VERSION 5.8 ;
BUSBITCHARS "[]" ;
DIVIDERCHAR "/" ;
CLEARANCEMEASURE EUCLIDEAN ;

SITE gt2_6t
    SIZE 0.0420 BY 0.1440 ;
    CLASS CORE ;
    SYMMETRY Y ;
END gt2_6t

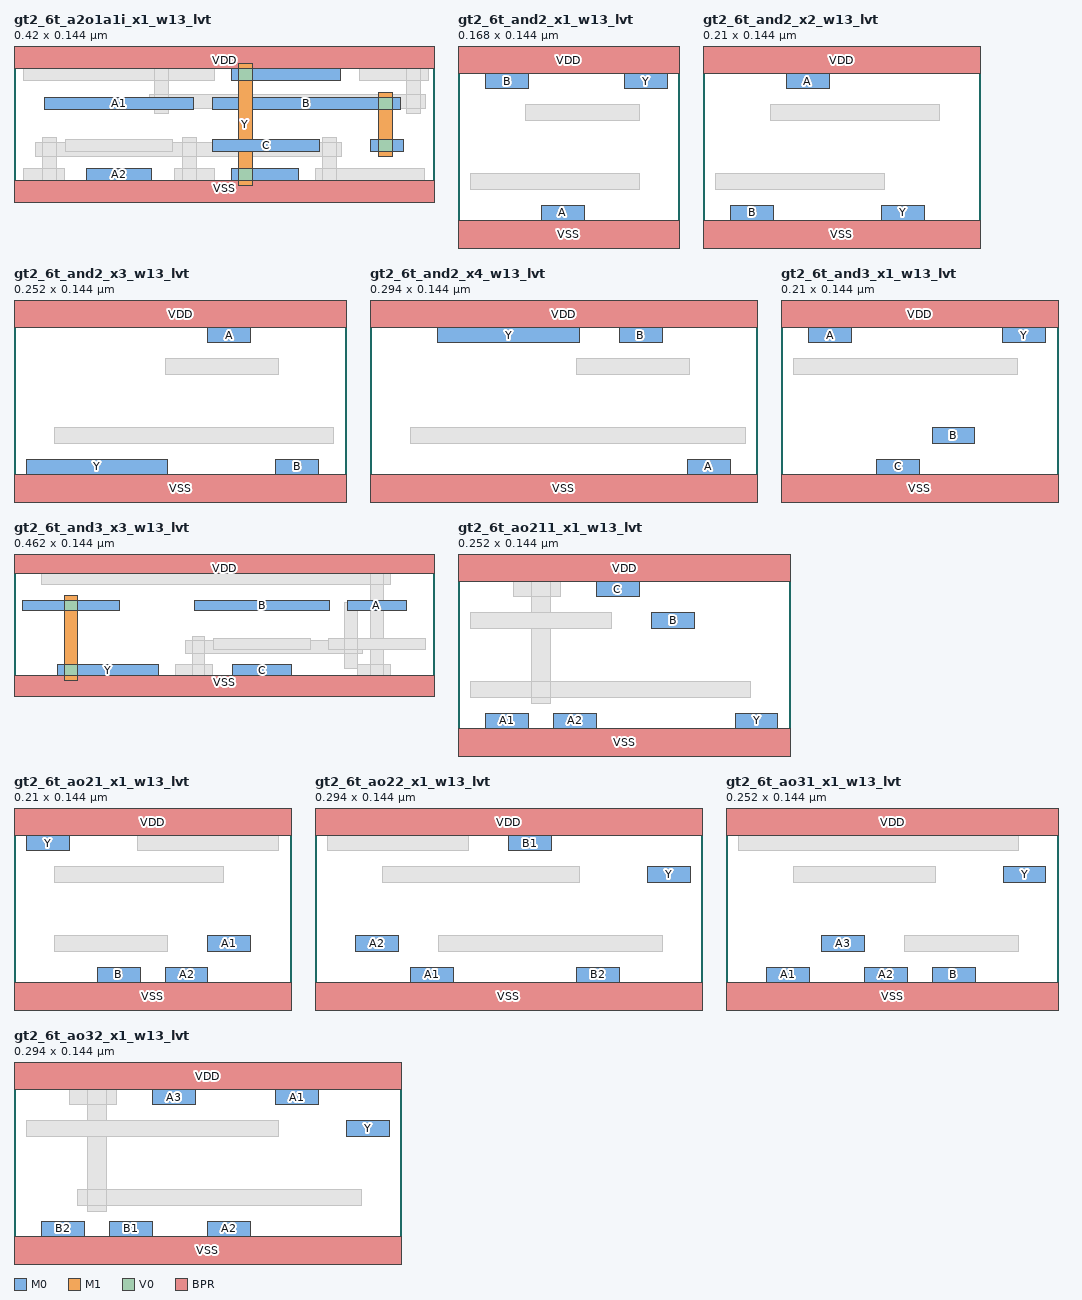
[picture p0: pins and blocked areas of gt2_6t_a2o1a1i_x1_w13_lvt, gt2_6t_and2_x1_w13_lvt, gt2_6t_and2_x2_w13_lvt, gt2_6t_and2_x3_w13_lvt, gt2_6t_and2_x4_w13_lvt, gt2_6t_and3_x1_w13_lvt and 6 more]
MACRO gt2_6t_a2o1a1i_x1_w13_lvt
  CLASS CORE ;
  ORIGIN 0 0 ;
  FOREIGN gt2_6t_a2o1a1i_x1_w13_lvt 0 0 ;
  SIZE 0.4200 BY 0.1440 ;
  SYMMETRY X Y ;
  SITE gt2_6t ;
  PIN A1
    DIRECTION INPUT ;
    USE SIGNAL ;
    PORT
      LAYER M0 ;
        RECT 0.0305 0.0870 0.1795 0.0990 ;
    END
  END A1
  PIN A2
    DIRECTION INPUT ;
    USE SIGNAL ;
    PORT
      LAYER M0 ;
        RECT 0.0725 0.0160 0.1375 0.0280 ;
    END
  END A2
  PIN B
    DIRECTION INPUT ;
    USE SIGNAL ;
    PORT
      LAYER M1 ;
        RECT 0.3640 0.0400 0.3780 0.1040 ;
      LAYER M0 ;
        RECT 0.3560 0.0450 0.3895 0.0570 ;
        RECT 0.1985 0.0870 0.3860 0.0990 ;
      LAYER V0 ;
        RECT 0.3640 0.0450 0.3780 0.0570 ;
        RECT 0.3640 0.0870 0.3780 0.0990 ;
    END
  END B
  PIN C
    DIRECTION INPUT ;
    USE SIGNAL ;
    PORT
      LAYER M0 ;
        RECT 0.1985 0.0450 0.3055 0.0570 ;
    END
  END C
  PIN Y
    DIRECTION OUTPUT ;
    USE SIGNAL ;
    PORT
      LAYER M1 ;
        RECT 0.2240 0.0110 0.2380 0.1330 ;
      LAYER M0 ;
        RECT 0.2175 0.0160 0.2845 0.0280 ;
        RECT 0.2175 0.1160 0.3265 0.1280 ;
      LAYER V0 ;
        RECT 0.2240 0.0160 0.2380 0.0280 ;
        RECT 0.2240 0.1160 0.2380 0.1280 ;
    END
  END Y
  PIN VDD
    DIRECTION INOUT ;
    USE POWER ;
    SHAPE ABUTMENT ;
    PORT
      LAYER BPR ;
        RECT 0.0000 0.1280 0.4200 0.1600 ;
    END
  END VDD
  PIN VSS
    DIRECTION INOUT ;
    USE GROUND ;
    SHAPE ABUTMENT ;
    PORT
      LAYER BPR ;
        RECT 0.0000 -0.0160 0.4200 0.0160 ;
    END
  END VSS
  OBS
    LAYER M2 ;
      RECT 0.0210 0.0400 0.3270 0.0540 ;
      RECT 0.1350 0.0880 0.4110 0.1020 ;
    LAYER M1 ;
      RECT 0.0280 0.0110 0.0420 0.0590 ;
      RECT 0.1680 0.0110 0.1820 0.0590 ;
      RECT 0.3080 0.0110 0.3220 0.0590 ;
      RECT 0.1400 0.0830 0.1540 0.1330 ;
      RECT 0.3920 0.0830 0.4060 0.1330 ;
    LAYER M0 ;
      RECT 0.0095 0.0160 0.0500 0.0280 ;
      RECT 0.1600 0.0160 0.2005 0.0280 ;
      RECT 0.3015 0.0160 0.4105 0.0280 ;
      RECT 0.0515 0.0450 0.1585 0.0570 ;
      RECT 0.0095 0.1160 0.2005 0.1280 ;
      RECT 0.3455 0.1160 0.4140 0.1280 ;
    LAYER V1 ;
      RECT 0.0280 0.0400 0.0420 0.0540 ;
      RECT 0.1680 0.0400 0.1820 0.0540 ;
      RECT 0.3080 0.0400 0.3220 0.0540 ;
      RECT 0.1400 0.0880 0.1540 0.1020 ;
      RECT 0.3920 0.0880 0.4060 0.1020 ;
    LAYER V0 ;
      RECT 0.0280 0.0160 0.0420 0.0280 ;
      RECT 0.1680 0.0160 0.1820 0.0280 ;
      RECT 0.3080 0.0160 0.3220 0.0280 ;
      RECT 0.1400 0.1160 0.1540 0.1280 ;
      RECT 0.3920 0.1160 0.4060 0.1280 ;
  END
END gt2_6t_a2o1a1i_x1_w13_lvt

MACRO gt2_6t_and2_x1_w13_lvt
  CLASS CORE ;
  ORIGIN 0 0 ;
  FOREIGN gt2_6t_and2_x1_w13_lvt 0 0 ;
  SIZE 0.1680 BY 0.1440 ;
  SYMMETRY X Y ;
  SITE gt2_6t ;
  PIN A
    DIRECTION INPUT ;
    USE SIGNAL ;
    PORT
      LAYER M0 ;
        RECT 0.0630 0.0160 0.0955 0.0280 ;
    END
  END A
  PIN B
    DIRECTION INPUT ;
    USE SIGNAL ;
    PORT
      LAYER M0 ;
        RECT 0.0210 0.1160 0.0535 0.1280 ;
    END
  END B
  PIN Y
    DIRECTION OUTPUT ;
    USE SIGNAL ;
    PORT
      LAYER M0 ;
        RECT 0.1260 0.1160 0.1585 0.1280 ;
    END
  END Y
  PIN VDD
    DIRECTION INOUT ;
    USE POWER ;
    SHAPE ABUTMENT ;
    PORT
      LAYER BPR ;
        RECT 0.0000 0.1280 0.1680 0.1600 ;
    END
  END VDD
  PIN VSS
    DIRECTION INOUT ;
    USE GROUND ;
    SHAPE ABUTMENT ;
    PORT
      LAYER BPR ;
        RECT 0.0000 -0.0160 0.1680 0.0160 ;
    END
  END VSS
  OBS
    LAYER M0 ;
      RECT 0.0095 0.0400 0.1375 0.0520 ;
      RECT 0.0515 0.0920 0.1375 0.1040 ;
  END
END gt2_6t_and2_x1_w13_lvt

MACRO gt2_6t_and2_x2_w13_lvt
  CLASS CORE ;
  ORIGIN 0 0 ;
  FOREIGN gt2_6t_and2_x2_w13_lvt 0 0 ;
  SIZE 0.2100 BY 0.1440 ;
  SYMMETRY X Y ;
  SITE gt2_6t ;
  PIN A
    DIRECTION INPUT ;
    USE SIGNAL ;
    PORT
      LAYER M0 ;
        RECT 0.0630 0.1160 0.0955 0.1280 ;
    END
  END A
  PIN B
    DIRECTION INPUT ;
    USE SIGNAL ;
    PORT
      LAYER M0 ;
        RECT 0.0210 0.0160 0.0535 0.0280 ;
    END
  END B
  PIN Y
    DIRECTION OUTPUT ;
    USE SIGNAL ;
    PORT
      LAYER M0 ;
        RECT 0.1355 0.0160 0.1680 0.0280 ;
    END
  END Y
  PIN VDD
    DIRECTION INOUT ;
    USE POWER ;
    SHAPE ABUTMENT ;
    PORT
      LAYER BPR ;
        RECT 0.0000 0.1280 0.2100 0.1600 ;
    END
  END VDD
  PIN VSS
    DIRECTION INOUT ;
    USE GROUND ;
    SHAPE ABUTMENT ;
    PORT
      LAYER BPR ;
        RECT 0.0000 -0.0160 0.2100 0.0160 ;
    END
  END VSS
  OBS
    LAYER M0 ;
      RECT 0.0095 0.0400 0.1375 0.0520 ;
      RECT 0.0515 0.0920 0.1795 0.1040 ;
  END
END gt2_6t_and2_x2_w13_lvt

MACRO gt2_6t_and2_x3_w13_lvt
  CLASS CORE ;
  ORIGIN 0 0 ;
  FOREIGN gt2_6t_and2_x3_w13_lvt 0 0 ;
  SIZE 0.2520 BY 0.1440 ;
  SYMMETRY X Y ;
  SITE gt2_6t ;
  PIN A
    DIRECTION INPUT ;
    USE SIGNAL ;
    PORT
      LAYER M0 ;
        RECT 0.1470 0.1160 0.1795 0.1280 ;
    END
  END A
  PIN B
    DIRECTION INPUT ;
    USE SIGNAL ;
    PORT
      LAYER M0 ;
        RECT 0.1985 0.0160 0.2310 0.0280 ;
    END
  END B
  PIN Y
    DIRECTION OUTPUT ;
    USE SIGNAL ;
    PORT
      LAYER M0 ;
        RECT 0.0095 0.0160 0.1165 0.0280 ;
    END
  END Y
  PIN VDD
    DIRECTION INOUT ;
    USE POWER ;
    SHAPE ABUTMENT ;
    PORT
      LAYER BPR ;
        RECT 0.0000 0.1280 0.2520 0.1600 ;
    END
  END VDD
  PIN VSS
    DIRECTION INOUT ;
    USE GROUND ;
    SHAPE ABUTMENT ;
    PORT
      LAYER BPR ;
        RECT 0.0000 -0.0160 0.2520 0.0160 ;
    END
  END VSS
  OBS
    LAYER M0 ;
      RECT 0.0305 0.0400 0.2425 0.0520 ;
      RECT 0.1145 0.0920 0.2005 0.1040 ;
  END
END gt2_6t_and2_x3_w13_lvt

MACRO gt2_6t_and2_x4_w13_lvt
  CLASS CORE ;
  ORIGIN 0 0 ;
  FOREIGN gt2_6t_and2_x4_w13_lvt 0 0 ;
  SIZE 0.2940 BY 0.1440 ;
  SYMMETRY X Y ;
  SITE gt2_6t ;
  PIN A
    DIRECTION INPUT ;
    USE SIGNAL ;
    PORT
      LAYER M0 ;
        RECT 0.2405 0.0160 0.2730 0.0280 ;
    END
  END A
  PIN B
    DIRECTION INPUT ;
    USE SIGNAL ;
    PORT
      LAYER M0 ;
        RECT 0.1890 0.1160 0.2215 0.1280 ;
    END
  END B
  PIN Y
    DIRECTION OUTPUT ;
    USE SIGNAL ;
    PORT
      LAYER M0 ;
        RECT 0.0515 0.1160 0.1585 0.1280 ;
    END
  END Y
  PIN VDD
    DIRECTION INOUT ;
    USE POWER ;
    SHAPE ABUTMENT ;
    PORT
      LAYER BPR ;
        RECT 0.0000 0.1280 0.2940 0.1600 ;
    END
  END VDD
  PIN VSS
    DIRECTION INOUT ;
    USE GROUND ;
    SHAPE ABUTMENT ;
    PORT
      LAYER BPR ;
        RECT 0.0000 -0.0160 0.2940 0.0160 ;
    END
  END VSS
  OBS
    LAYER M0 ;
      RECT 0.0305 0.0400 0.2845 0.0520 ;
      RECT 0.1565 0.0920 0.2425 0.1040 ;
  END
END gt2_6t_and2_x4_w13_lvt

MACRO gt2_6t_and3_x1_w13_lvt
  CLASS CORE ;
  ORIGIN 0 0 ;
  FOREIGN gt2_6t_and3_x1_w13_lvt 0 0 ;
  SIZE 0.2100 BY 0.1440 ;
  SYMMETRY X Y ;
  SITE gt2_6t ;
  PIN A
    DIRECTION INPUT ;
    USE SIGNAL ;
    PORT
      LAYER M0 ;
        RECT 0.0210 0.1160 0.0535 0.1280 ;
    END
  END A
  PIN B
    DIRECTION INPUT ;
    USE SIGNAL ;
    PORT
      LAYER M0 ;
        RECT 0.1145 0.0400 0.1470 0.0520 ;
    END
  END B
  PIN C
    DIRECTION INPUT ;
    USE SIGNAL ;
    PORT
      LAYER M0 ;
        RECT 0.0725 0.0160 0.1050 0.0280 ;
    END
  END C
  PIN Y
    DIRECTION OUTPUT ;
    USE SIGNAL ;
    PORT
      LAYER M0 ;
        RECT 0.1680 0.1160 0.2005 0.1280 ;
    END
  END Y
  PIN VDD
    DIRECTION INOUT ;
    USE POWER ;
    SHAPE ABUTMENT ;
    PORT
      LAYER BPR ;
        RECT 0.0000 0.1280 0.2100 0.1600 ;
    END
  END VDD
  PIN VSS
    DIRECTION INOUT ;
    USE GROUND ;
    SHAPE ABUTMENT ;
    PORT
      LAYER BPR ;
        RECT 0.0000 -0.0160 0.2100 0.0160 ;
    END
  END VSS
  OBS
    LAYER M0 ;
      RECT 0.0095 0.0920 0.1795 0.1040 ;
  END
END gt2_6t_and3_x1_w13_lvt

MACRO gt2_6t_and3_x3_w13_lvt
  CLASS CORE ;
  ORIGIN 0 0 ;
  FOREIGN gt2_6t_and3_x3_w13_lvt 0 0 ;
  SIZE 0.4620 BY 0.1440 ;
  SYMMETRY X Y ;
  SITE gt2_6t ;
  PIN A
    DIRECTION INPUT ;
    USE SIGNAL ;
    PORT
      LAYER M0 ;
        RECT 0.3665 0.0870 0.4315 0.0990 ;
    END
  END A
  PIN B
    DIRECTION INPUT ;
    USE SIGNAL ;
    PORT
      LAYER M0 ;
        RECT 0.1985 0.0870 0.3475 0.0990 ;
    END
  END B
  PIN C
    DIRECTION INPUT ;
    USE SIGNAL ;
    PORT
      LAYER M0 ;
        RECT 0.2405 0.0160 0.3055 0.0280 ;
    END
  END C
  PIN Y
    DIRECTION OUTPUT ;
    USE SIGNAL ;
    PORT
      LAYER M1 ;
        RECT 0.0560 0.0110 0.0700 0.1040 ;
      LAYER M0 ;
        RECT 0.0480 0.0160 0.1585 0.0280 ;
        RECT 0.0095 0.0870 0.1165 0.0990 ;
      LAYER V0 ;
        RECT 0.0560 0.0160 0.0700 0.0280 ;
        RECT 0.0560 0.0870 0.0700 0.0990 ;
    END
  END Y
  PIN VDD
    DIRECTION INOUT ;
    USE POWER ;
    SHAPE ABUTMENT ;
    PORT
      LAYER BPR ;
        RECT 0.0000 0.1280 0.4620 0.1600 ;
    END
  END VDD
  PIN VSS
    DIRECTION INOUT ;
    USE GROUND ;
    SHAPE ABUTMENT ;
    PORT
      LAYER BPR ;
        RECT 0.0000 -0.0160 0.4620 0.0160 ;
    END
  END VSS
  OBS
    LAYER M2 ;
      RECT 0.1890 0.0400 0.3830 0.0540 ;
    LAYER M1 ;
      RECT 0.1960 0.0110 0.2100 0.0590 ;
      RECT 0.3640 0.0240 0.3780 0.0960 ;
      RECT 0.3920 0.0110 0.4060 0.1330 ;
    LAYER M0 ;
      RECT 0.1775 0.0160 0.2180 0.0280 ;
      RECT 0.3455 0.0450 0.4525 0.0570 ;
      RECT 0.2195 0.0450 0.3265 0.0570 ;
      RECT 0.3780 0.0160 0.4140 0.0280 ;
      RECT 0.0305 0.1160 0.4140 0.1280 ;
    LAYER V1 ;
      RECT 0.1960 0.0400 0.2100 0.0540 ;
      RECT 0.3640 0.0400 0.3780 0.0540 ;
    LAYER V0 ;
      RECT 0.1960 0.0160 0.2100 0.0280 ;
      RECT 0.3640 0.0450 0.3780 0.0570 ;
      RECT 0.3920 0.0160 0.4060 0.0280 ;
      RECT 0.3920 0.1160 0.4060 0.1280 ;
  END
END gt2_6t_and3_x3_w13_lvt

MACRO gt2_6t_ao211_x1_w13_lvt
  CLASS CORE ;
  ORIGIN 0 0 ;
  FOREIGN gt2_6t_ao211_x1_w13_lvt 0 0 ;
  SIZE 0.2520 BY 0.1440 ;
  SYMMETRY X Y ;
  SITE gt2_6t ;
  PIN A1
    DIRECTION INPUT ;
    USE SIGNAL ;
    PORT
      LAYER M0 ;
        RECT 0.0210 0.0160 0.0535 0.0280 ;
    END
  END A1
  PIN A2
    DIRECTION INPUT ;
    USE SIGNAL ;
    PORT
      LAYER M0 ;
        RECT 0.0725 0.0160 0.1050 0.0280 ;
    END
  END A2
  PIN B
    DIRECTION INPUT ;
    USE SIGNAL ;
    PORT
      LAYER M0 ;
        RECT 0.1470 0.0920 0.1795 0.1040 ;
    END
  END B
  PIN C
    DIRECTION INPUT ;
    USE SIGNAL ;
    PORT
      LAYER M0 ;
        RECT 0.1050 0.1160 0.1375 0.1280 ;
    END
  END C
  PIN Y
    DIRECTION OUTPUT ;
    USE SIGNAL ;
    PORT
      LAYER M0 ;
        RECT 0.2100 0.0160 0.2425 0.0280 ;
    END
  END Y
  PIN VDD
    DIRECTION INOUT ;
    USE POWER ;
    SHAPE ABUTMENT ;
    PORT
      LAYER BPR ;
        RECT 0.0000 0.1280 0.2520 0.1600 ;
    END
  END VDD
  PIN VSS
    DIRECTION INOUT ;
    USE GROUND ;
    SHAPE ABUTMENT ;
    PORT
      LAYER BPR ;
        RECT 0.0000 -0.0160 0.2520 0.0160 ;
    END
  END VSS
  OBS
    LAYER M1 ;
      RECT 0.0560 0.0350 0.0700 0.1330 ;
    LAYER M0 ;
      RECT 0.0095 0.0400 0.2215 0.0520 ;
      RECT 0.0420 0.1160 0.0780 0.1280 ;
      RECT 0.0095 0.0920 0.1165 0.1040 ;
    LAYER V0 ;
      RECT 0.0560 0.0400 0.0700 0.0520 ;
      RECT 0.0560 0.1160 0.0700 0.1280 ;
  END
END gt2_6t_ao211_x1_w13_lvt

MACRO gt2_6t_ao21_x1_w13_lvt
  CLASS CORE ;
  ORIGIN 0 0 ;
  FOREIGN gt2_6t_ao21_x1_w13_lvt 0 0 ;
  SIZE 0.2100 BY 0.1440 ;
  SYMMETRY X Y ;
  SITE gt2_6t ;
  PIN A1
    DIRECTION INPUT ;
    USE SIGNAL ;
    PORT
      LAYER M0 ;
        RECT 0.1470 0.0400 0.1795 0.0520 ;
    END
  END A1
  PIN A2
    DIRECTION INPUT ;
    USE SIGNAL ;
    PORT
      LAYER M0 ;
        RECT 0.1145 0.0160 0.1470 0.0280 ;
    END
  END A2
  PIN B
    DIRECTION INPUT ;
    USE SIGNAL ;
    PORT
      LAYER M0 ;
        RECT 0.0630 0.0160 0.0955 0.0280 ;
    END
  END B
  PIN Y
    DIRECTION OUTPUT ;
    USE SIGNAL ;
    PORT
      LAYER M0 ;
        RECT 0.0095 0.1160 0.0420 0.1280 ;
    END
  END Y
  PIN VDD
    DIRECTION INOUT ;
    USE POWER ;
    SHAPE ABUTMENT ;
    PORT
      LAYER BPR ;
        RECT 0.0000 0.1280 0.2100 0.1600 ;
    END
  END VDD
  PIN VSS
    DIRECTION INOUT ;
    USE GROUND ;
    SHAPE ABUTMENT ;
    PORT
      LAYER BPR ;
        RECT 0.0000 -0.0160 0.2100 0.0160 ;
    END
  END VSS
  OBS
    LAYER M0 ;
      RECT 0.0305 0.0400 0.1165 0.0520 ;
      RECT 0.0305 0.0920 0.1585 0.1040 ;
      RECT 0.0935 0.1160 0.2005 0.1280 ;
  END
END gt2_6t_ao21_x1_w13_lvt

MACRO gt2_6t_ao22_x1_w13_lvt
  CLASS CORE ;
  ORIGIN 0 0 ;
  FOREIGN gt2_6t_ao22_x1_w13_lvt 0 0 ;
  SIZE 0.2940 BY 0.1440 ;
  SYMMETRY X Y ;
  SITE gt2_6t ;
  PIN A1
    DIRECTION INPUT ;
    USE SIGNAL ;
    PORT
      LAYER M0 ;
        RECT 0.0725 0.0160 0.1050 0.0280 ;
    END
  END A1
  PIN A2
    DIRECTION INPUT ;
    USE SIGNAL ;
    PORT
      LAYER M0 ;
        RECT 0.0305 0.0400 0.0630 0.0520 ;
    END
  END A2
  PIN B1
    DIRECTION INPUT ;
    USE SIGNAL ;
    PORT
      LAYER M0 ;
        RECT 0.1470 0.1160 0.1795 0.1280 ;
    END
  END B1
  PIN B2
    DIRECTION INPUT ;
    USE SIGNAL ;
    PORT
      LAYER M0 ;
        RECT 0.1985 0.0160 0.2310 0.0280 ;
    END
  END B2
  PIN Y
    DIRECTION OUTPUT ;
    USE SIGNAL ;
    PORT
      LAYER M0 ;
        RECT 0.2520 0.0920 0.2845 0.1040 ;
    END
  END Y
  PIN VDD
    DIRECTION INOUT ;
    USE POWER ;
    SHAPE ABUTMENT ;
    PORT
      LAYER BPR ;
        RECT 0.0000 0.1280 0.2940 0.1600 ;
    END
  END VDD
  PIN VSS
    DIRECTION INOUT ;
    USE GROUND ;
    SHAPE ABUTMENT ;
    PORT
      LAYER BPR ;
        RECT 0.0000 -0.0160 0.2940 0.0160 ;
    END
  END VSS
  OBS
    LAYER M0 ;
      RECT 0.0935 0.0400 0.2635 0.0520 ;
      RECT 0.0095 0.1160 0.1165 0.1280 ;
      RECT 0.0515 0.0920 0.2005 0.1040 ;
  END
END gt2_6t_ao22_x1_w13_lvt

MACRO gt2_6t_ao31_x1_w13_lvt
  CLASS CORE ;
  ORIGIN 0 0 ;
  FOREIGN gt2_6t_ao31_x1_w13_lvt 0 0 ;
  SIZE 0.2520 BY 0.1440 ;
  SYMMETRY X Y ;
  SITE gt2_6t ;
  PIN A1
    DIRECTION INPUT ;
    USE SIGNAL ;
    PORT
      LAYER M0 ;
        RECT 0.0305 0.0160 0.0630 0.0280 ;
    END
  END A1
  PIN A2
    DIRECTION INPUT ;
    USE SIGNAL ;
    PORT
      LAYER M0 ;
        RECT 0.1050 0.0160 0.1375 0.0280 ;
    END
  END A2
  PIN A3
    DIRECTION INPUT ;
    USE SIGNAL ;
    PORT
      LAYER M0 ;
        RECT 0.0725 0.0400 0.1050 0.0520 ;
    END
  END A3
  PIN B
    DIRECTION INPUT ;
    USE SIGNAL ;
    PORT
      LAYER M0 ;
        RECT 0.1565 0.0160 0.1890 0.0280 ;
    END
  END B
  PIN Y
    DIRECTION OUTPUT ;
    USE SIGNAL ;
    PORT
      LAYER M0 ;
        RECT 0.2100 0.0920 0.2425 0.1040 ;
    END
  END Y
  PIN VDD
    DIRECTION INOUT ;
    USE POWER ;
    SHAPE ABUTMENT ;
    PORT
      LAYER BPR ;
        RECT 0.0000 0.1280 0.2520 0.1600 ;
    END
  END VDD
  PIN VSS
    DIRECTION INOUT ;
    USE GROUND ;
    SHAPE ABUTMENT ;
    PORT
      LAYER BPR ;
        RECT 0.0000 -0.0160 0.2520 0.0160 ;
    END
  END VSS
  OBS
    LAYER M0 ;
      RECT 0.1355 0.0400 0.2215 0.0520 ;
      RECT 0.0095 0.1160 0.2215 0.1280 ;
      RECT 0.0515 0.0920 0.1585 0.1040 ;
  END
END gt2_6t_ao31_x1_w13_lvt

MACRO gt2_6t_ao32_x1_w13_lvt
  CLASS CORE ;
  ORIGIN 0 0 ;
  FOREIGN gt2_6t_ao32_x1_w13_lvt 0 0 ;
  SIZE 0.2940 BY 0.1440 ;
  SYMMETRY X Y ;
  SITE gt2_6t ;
  PIN A1
    DIRECTION INPUT ;
    USE SIGNAL ;
    PORT
      LAYER M0 ;
        RECT 0.1985 0.1160 0.2310 0.1280 ;
    END
  END A1
  PIN A2
    DIRECTION INPUT ;
    USE SIGNAL ;
    PORT
      LAYER M0 ;
        RECT 0.1470 0.0160 0.1795 0.0280 ;
    END
  END A2
  PIN A3
    DIRECTION INPUT ;
    USE SIGNAL ;
    PORT
      LAYER M0 ;
        RECT 0.1050 0.1160 0.1375 0.1280 ;
    END
  END A3
  PIN B1
    DIRECTION INPUT ;
    USE SIGNAL ;
    PORT
      LAYER M0 ;
        RECT 0.0725 0.0160 0.1050 0.0280 ;
    END
  END B1
  PIN B2
    DIRECTION INPUT ;
    USE SIGNAL ;
    PORT
      LAYER M0 ;
        RECT 0.0210 0.0160 0.0535 0.0280 ;
    END
  END B2
  PIN Y
    DIRECTION OUTPUT ;
    USE SIGNAL ;
    PORT
      LAYER M0 ;
        RECT 0.2520 0.0920 0.2845 0.1040 ;
    END
  END Y
  PIN VDD
    DIRECTION INOUT ;
    USE POWER ;
    SHAPE ABUTMENT ;
    PORT
      LAYER BPR ;
        RECT 0.0000 0.1280 0.2940 0.1600 ;
    END
  END VDD
  PIN VSS
    DIRECTION INOUT ;
    USE GROUND ;
    SHAPE ABUTMENT ;
    PORT
      LAYER BPR ;
        RECT 0.0000 -0.0160 0.2940 0.0160 ;
    END
  END VSS
  OBS
    LAYER M1 ;
      RECT 0.0560 0.0350 0.0700 0.1330 ;
    LAYER M0 ;
      RECT 0.0480 0.0400 0.2635 0.0520 ;
      RECT 0.0420 0.1160 0.0780 0.1280 ;
      RECT 0.0095 0.0920 0.2005 0.1040 ;
    LAYER V0 ;
      RECT 0.0560 0.0400 0.0700 0.0520 ;
      RECT 0.0560 0.1160 0.0700 0.1280 ;
  END
END gt2_6t_ao32_x1_w13_lvt

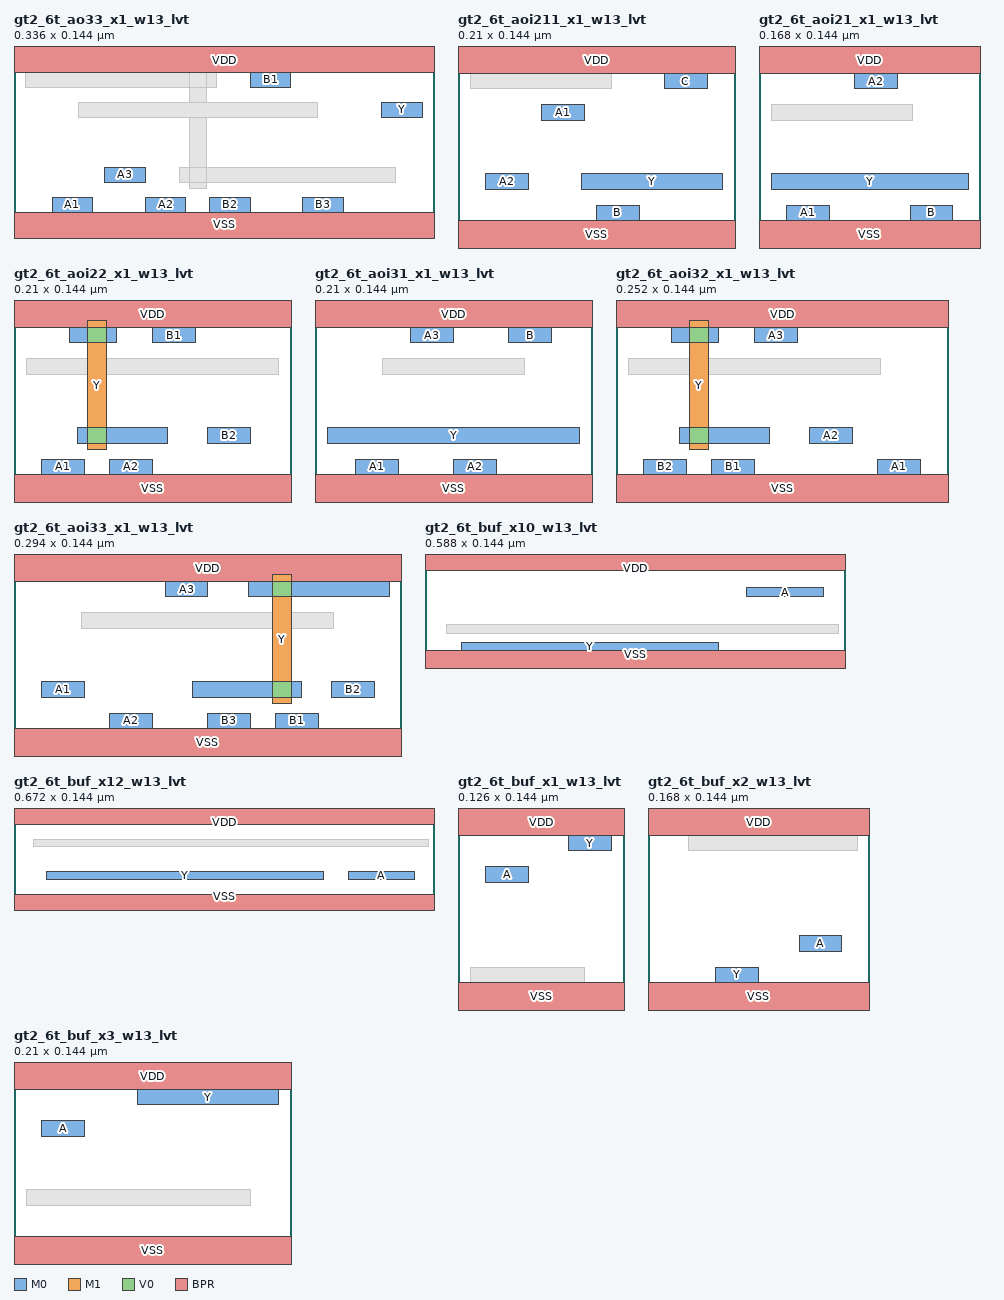
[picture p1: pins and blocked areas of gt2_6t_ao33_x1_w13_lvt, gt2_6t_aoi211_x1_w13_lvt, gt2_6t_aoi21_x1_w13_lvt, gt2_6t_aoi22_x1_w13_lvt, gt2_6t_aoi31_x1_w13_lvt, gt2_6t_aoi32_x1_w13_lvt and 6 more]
MACRO gt2_6t_ao33_x1_w13_lvt
  CLASS CORE ;
  ORIGIN 0 0 ;
  FOREIGN gt2_6t_ao33_x1_w13_lvt 0 0 ;
  SIZE 0.3360 BY 0.1440 ;
  SYMMETRY X Y ;
  SITE gt2_6t ;
  PIN A1
    DIRECTION INPUT ;
    USE SIGNAL ;
    PORT
      LAYER M0 ;
        RECT 0.0305 0.0160 0.0630 0.0280 ;
    END
  END A1
  PIN A2
    DIRECTION INPUT ;
    USE SIGNAL ;
    PORT
      LAYER M0 ;
        RECT 0.1050 0.0160 0.1375 0.0280 ;
    END
  END A2
  PIN A3
    DIRECTION INPUT ;
    USE SIGNAL ;
    PORT
      LAYER M0 ;
        RECT 0.0725 0.0400 0.1050 0.0520 ;
    END
  END A3
  PIN B1
    DIRECTION INPUT ;
    USE SIGNAL ;
    PORT
      LAYER M0 ;
        RECT 0.1890 0.1160 0.2215 0.1280 ;
    END
  END B1
  PIN B2
    DIRECTION INPUT ;
    USE SIGNAL ;
    PORT
      LAYER M0 ;
        RECT 0.1565 0.0160 0.1890 0.0280 ;
    END
  END B2
  PIN B3
    DIRECTION INPUT ;
    USE SIGNAL ;
    PORT
      LAYER M0 ;
        RECT 0.2310 0.0160 0.2635 0.0280 ;
    END
  END B3
  PIN Y
    DIRECTION OUTPUT ;
    USE SIGNAL ;
    PORT
      LAYER M0 ;
        RECT 0.2940 0.0920 0.3265 0.1040 ;
    END
  END Y
  PIN VDD
    DIRECTION INOUT ;
    USE POWER ;
    SHAPE ABUTMENT ;
    PORT
      LAYER BPR ;
        RECT 0.0000 0.1280 0.3360 0.1600 ;
    END
  END VDD
  PIN VSS
    DIRECTION INOUT ;
    USE GROUND ;
    SHAPE ABUTMENT ;
    PORT
      LAYER BPR ;
        RECT 0.0000 -0.0160 0.3360 0.0160 ;
    END
  END VSS
  OBS
    LAYER M1 ;
      RECT 0.1400 0.0350 0.1540 0.1330 ;
    LAYER M0 ;
      RECT 0.1320 0.0400 0.3055 0.0520 ;
      RECT 0.0095 0.1160 0.1620 0.1280 ;
      RECT 0.0515 0.0920 0.2425 0.1040 ;
    LAYER V0 ;
      RECT 0.1400 0.0400 0.1540 0.0520 ;
      RECT 0.1400 0.1160 0.1540 0.1280 ;
  END
END gt2_6t_ao33_x1_w13_lvt

MACRO gt2_6t_aoi211_x1_w13_lvt
  CLASS CORE ;
  ORIGIN 0 0 ;
  FOREIGN gt2_6t_aoi211_x1_w13_lvt 0 0 ;
  SIZE 0.2100 BY 0.1440 ;
  SYMMETRY X Y ;
  SITE gt2_6t ;
  PIN A1
    DIRECTION INPUT ;
    USE SIGNAL ;
    PORT
      LAYER M0 ;
        RECT 0.0630 0.0920 0.0955 0.1040 ;
    END
  END A1
  PIN A2
    DIRECTION INPUT ;
    USE SIGNAL ;
    PORT
      LAYER M0 ;
        RECT 0.0210 0.0400 0.0535 0.0520 ;
    END
  END A2
  PIN B
    DIRECTION INPUT ;
    USE SIGNAL ;
    PORT
      LAYER M0 ;
        RECT 0.1050 0.0160 0.1375 0.0280 ;
    END
  END B
  PIN C
    DIRECTION INPUT ;
    USE SIGNAL ;
    PORT
      LAYER M0 ;
        RECT 0.1565 0.1160 0.1890 0.1280 ;
    END
  END C
  PIN Y
    DIRECTION OUTPUT ;
    USE SIGNAL ;
    PORT
      LAYER M0 ;
        RECT 0.0935 0.0400 0.2005 0.0520 ;
    END
  END Y
  PIN VDD
    DIRECTION INOUT ;
    USE POWER ;
    SHAPE ABUTMENT ;
    PORT
      LAYER BPR ;
        RECT 0.0000 0.1280 0.2100 0.1600 ;
    END
  END VDD
  PIN VSS
    DIRECTION INOUT ;
    USE GROUND ;
    SHAPE ABUTMENT ;
    PORT
      LAYER BPR ;
        RECT 0.0000 -0.0160 0.2100 0.0160 ;
    END
  END VSS
  OBS
    LAYER M0 ;
      RECT 0.0095 0.1160 0.1165 0.1280 ;
  END
END gt2_6t_aoi211_x1_w13_lvt

MACRO gt2_6t_aoi21_x1_w13_lvt
  CLASS CORE ;
  ORIGIN 0 0 ;
  FOREIGN gt2_6t_aoi21_x1_w13_lvt 0 0 ;
  SIZE 0.1680 BY 0.1440 ;
  SYMMETRY X Y ;
  SITE gt2_6t ;
  PIN A1
    DIRECTION INPUT ;
    USE SIGNAL ;
    PORT
      LAYER M0 ;
        RECT 0.0210 0.0160 0.0535 0.0280 ;
    END
  END A1
  PIN A2
    DIRECTION INPUT ;
    USE SIGNAL ;
    PORT
      LAYER M0 ;
        RECT 0.0725 0.1160 0.1050 0.1280 ;
    END
  END A2
  PIN B
    DIRECTION INPUT ;
    USE SIGNAL ;
    PORT
      LAYER M0 ;
        RECT 0.1145 0.0160 0.1470 0.0280 ;
    END
  END B
  PIN Y
    DIRECTION OUTPUT ;
    USE SIGNAL ;
    PORT
      LAYER M0 ;
        RECT 0.0095 0.0400 0.1585 0.0520 ;
    END
  END Y
  PIN VDD
    DIRECTION INOUT ;
    USE POWER ;
    SHAPE ABUTMENT ;
    PORT
      LAYER BPR ;
        RECT 0.0000 0.1280 0.1680 0.1600 ;
    END
  END VDD
  PIN VSS
    DIRECTION INOUT ;
    USE GROUND ;
    SHAPE ABUTMENT ;
    PORT
      LAYER BPR ;
        RECT 0.0000 -0.0160 0.1680 0.0160 ;
    END
  END VSS
  OBS
    LAYER M0 ;
      RECT 0.0095 0.0920 0.1165 0.1040 ;
  END
END gt2_6t_aoi21_x1_w13_lvt


MACRO gt2_6t_aoi22_x1_w13_lvt
  CLASS CORE ;
  ORIGIN 0 0 ;
  FOREIGN gt2_6t_aoi22_x1_w13_lvt 0 0 ;
  SIZE 0.2100 BY 0.1440 ;
  SYMMETRY X Y ;
  SITE gt2_6t ;
  PIN A1
    DIRECTION INPUT ;
    USE SIGNAL ;
    PORT
      LAYER M0 ;
        RECT 0.0210 0.0160 0.0535 0.0280 ;
    END
  END A1
  PIN A2
    DIRECTION INPUT ;
    USE SIGNAL ;
    PORT
      LAYER M0 ;
        RECT 0.0725 0.0160 0.1050 0.0280 ;
    END
  END A2
  PIN B1
    DIRECTION INPUT ;
    USE SIGNAL ;
    PORT
      LAYER M0 ;
        RECT 0.1050 0.1160 0.1375 0.1280 ;
    END
  END B1
  PIN B2
    DIRECTION INPUT ;
    USE SIGNAL ;
    PORT
      LAYER M0 ;
        RECT 0.1470 0.0400 0.1795 0.0520 ;
    END
  END B2
  PIN Y
    DIRECTION OUTPUT ;
    USE SIGNAL ;
    PORT
      LAYER M1 ;
        RECT 0.0560 0.0350 0.0700 0.1330 ;
      LAYER M0 ;
        RECT 0.0480 0.0400 0.1165 0.0520 ;
        RECT 0.0420 0.1160 0.0780 0.1280 ;
      LAYER V0 ;
        RECT 0.0560 0.0400 0.0700 0.0520 ;
        RECT 0.0560 0.1160 0.0700 0.1280 ;
    END
  END Y
  PIN VDD
    DIRECTION INOUT ;
    USE POWER ;
    SHAPE ABUTMENT ;
    PORT
      LAYER BPR ;
        RECT 0.0000 0.1280 0.2100 0.1600 ;
    END
  END VDD
  PIN VSS
    DIRECTION INOUT ;
    USE GROUND ;
    SHAPE ABUTMENT ;
    PORT
      LAYER BPR ;
        RECT 0.0000 -0.0160 0.2100 0.0160 ;
    END
  END VSS
  OBS
    LAYER M0 ;
      RECT 0.0095 0.0920 0.2005 0.1040 ;
  END
END gt2_6t_aoi22_x1_w13_lvt


MACRO gt2_6t_aoi31_x1_w13_lvt
  CLASS CORE ;
  ORIGIN 0 0 ;
  FOREIGN gt2_6t_aoi31_x1_w13_lvt 0 0 ;
  SIZE 0.2100 BY 0.1440 ;
  SYMMETRY X Y ;
  SITE gt2_6t ;
  PIN A1
    DIRECTION INPUT ;
    USE SIGNAL ;
    PORT
      LAYER M0 ;
        RECT 0.0305 0.0160 0.0630 0.0280 ;
    END
  END A1
  PIN A2
    DIRECTION INPUT ;
    USE SIGNAL ;
    PORT
      LAYER M0 ;
        RECT 0.1050 0.0160 0.1375 0.0280 ;
    END
  END A2
  PIN A3
    DIRECTION INPUT ;
    USE SIGNAL ;
    PORT
      LAYER M0 ;
        RECT 0.0725 0.1160 0.1050 0.1280 ;
    END
  END A3
  PIN B
    DIRECTION INPUT ;
    USE SIGNAL ;
    PORT
      LAYER M0 ;
        RECT 0.1470 0.1160 0.1795 0.1280 ;
    END
  END B
  PIN Y
    DIRECTION OUTPUT ;
    USE SIGNAL ;
    PORT
      LAYER M0 ;
        RECT 0.0095 0.0400 0.2005 0.0520 ;
    END
  END Y
  PIN VDD
    DIRECTION INOUT ;
    USE POWER ;
    SHAPE ABUTMENT ;
    PORT
      LAYER BPR ;
        RECT 0.0000 0.1280 0.2100 0.1600 ;
    END
  END VDD
  PIN VSS
    DIRECTION INOUT ;
    USE GROUND ;
    SHAPE ABUTMENT ;
    PORT
      LAYER BPR ;
        RECT 0.0000 -0.0160 0.2100 0.0160 ;
    END
  END VSS
  OBS
    LAYER M0 ;
      RECT 0.0515 0.0920 0.1585 0.1040 ;
  END
END gt2_6t_aoi31_x1_w13_lvt

MACRO gt2_6t_aoi32_x1_w13_lvt
  CLASS CORE ;
  ORIGIN 0 0 ;
  FOREIGN gt2_6t_aoi32_x1_w13_lvt 0 0 ;
  SIZE 0.2520 BY 0.1440 ;
  SYMMETRY X Y ;
  SITE gt2_6t ;
  PIN A1
    DIRECTION INPUT ;
    USE SIGNAL ;
    PORT
      LAYER M0 ;
        RECT 0.1985 0.0160 0.2310 0.0280 ;
    END
  END A1
  PIN A2
    DIRECTION INPUT ;
    USE SIGNAL ;
    PORT
      LAYER M0 ;
        RECT 0.1470 0.0400 0.1795 0.0520 ;
    END
  END A2
  PIN A3
    DIRECTION INPUT ;
    USE SIGNAL ;
    PORT
      LAYER M0 ;
        RECT 0.1050 0.1160 0.1375 0.1280 ;
    END
  END A3
  PIN B1
    DIRECTION INPUT ;
    USE SIGNAL ;
    PORT
      LAYER M0 ;
        RECT 0.0725 0.0160 0.1050 0.0280 ;
    END
  END B1
  PIN B2
    DIRECTION INPUT ;
    USE SIGNAL ;
    PORT
      LAYER M0 ;
        RECT 0.0210 0.0160 0.0535 0.0280 ;
    END
  END B2
  PIN Y
    DIRECTION OUTPUT ;
    USE SIGNAL ;
    PORT
      LAYER M1 ;
        RECT 0.0560 0.0350 0.0700 0.1330 ;
      LAYER M0 ;
        RECT 0.0480 0.0400 0.1165 0.0520 ;
        RECT 0.0420 0.1160 0.0780 0.1280 ;
      LAYER V0 ;
        RECT 0.0560 0.0400 0.0700 0.0520 ;
        RECT 0.0560 0.1160 0.0700 0.1280 ;
    END
  END Y
  PIN VDD
    DIRECTION INOUT ;
    USE POWER ;
    SHAPE ABUTMENT ;
    PORT
      LAYER BPR ;
        RECT 0.0000 0.1280 0.2520 0.1600 ;
    END
  END VDD
  PIN VSS
    DIRECTION INOUT ;
    USE GROUND ;
    SHAPE ABUTMENT ;
    PORT
      LAYER BPR ;
        RECT 0.0000 -0.0160 0.2520 0.0160 ;
    END
  END VSS
  OBS
    LAYER M0 ;
      RECT 0.0095 0.0920 0.2005 0.1040 ;
  END
END gt2_6t_aoi32_x1_w13_lvt

MACRO gt2_6t_aoi33_x1_w13_lvt
  CLASS CORE ;
  ORIGIN 0 0 ;
  FOREIGN gt2_6t_aoi33_x1_w13_lvt 0 0 ;
  SIZE 0.2940 BY 0.1440 ;
  SYMMETRY X Y ;
  SITE gt2_6t ;
  PIN A1
    DIRECTION INPUT ;
    USE SIGNAL ;
    PORT
      LAYER M0 ;
        RECT 0.0210 0.0400 0.0535 0.0520 ;
    END
  END A1
  PIN A2
    DIRECTION INPUT ;
    USE SIGNAL ;
    PORT
      LAYER M0 ;
        RECT 0.0725 0.0160 0.1050 0.0280 ;
    END
  END A2
  PIN A3
    DIRECTION INPUT ;
    USE SIGNAL ;
    PORT
      LAYER M0 ;
        RECT 0.1145 0.1160 0.1470 0.1280 ;
    END
  END A3
  PIN B1
    DIRECTION INPUT ;
    USE SIGNAL ;
    PORT
      LAYER M0 ;
        RECT 0.1985 0.0160 0.2310 0.0280 ;
    END
  END B1
  PIN B2
    DIRECTION INPUT ;
    USE SIGNAL ;
    PORT
      LAYER M0 ;
        RECT 0.2405 0.0400 0.2730 0.0520 ;
    END
  END B2
  PIN B3
    DIRECTION INPUT ;
    USE SIGNAL ;
    PORT
      LAYER M0 ;
        RECT 0.1470 0.0160 0.1795 0.0280 ;
    END
  END B3
  PIN Y
    DIRECTION OUTPUT ;
    USE SIGNAL ;
    PORT
      LAYER M1 ;
        RECT 0.1960 0.0350 0.2100 0.1330 ;
      LAYER M0 ;
        RECT 0.1355 0.0400 0.2180 0.0520 ;
        RECT 0.1775 0.1160 0.2845 0.1280 ;
      LAYER V0 ;
        RECT 0.1960 0.0400 0.2100 0.0520 ;
        RECT 0.1960 0.1160 0.2100 0.1280 ;
    END
  END Y
  PIN VDD
    DIRECTION INOUT ;
    USE POWER ;
    SHAPE ABUTMENT ;
    PORT
      LAYER BPR ;
        RECT 0.0000 0.1280 0.2940 0.1600 ;
    END
  END VDD
  PIN VSS
    DIRECTION INOUT ;
    USE GROUND ;
    SHAPE ABUTMENT ;
    PORT
      LAYER BPR ;
        RECT 0.0000 -0.0160 0.2940 0.0160 ;
    END
  END VSS
  OBS
    LAYER M0 ;
      RECT 0.0515 0.0920 0.2425 0.1040 ;
  END
END gt2_6t_aoi33_x1_w13_lvt

MACRO gt2_6t_buf_x10_w13_lvt
  CLASS CORE ;
  ORIGIN 0 0 ;
  FOREIGN gt2_6t_buf_x10_w13_lvt 0 0 ;
  SIZE 0.5880 BY 0.1440 ;
  SYMMETRY X Y ;
  SITE gt2_6t ;
  PIN A
    DIRECTION INPUT ;
    USE SIGNAL ;
    PORT
      LAYER M0 ;
        RECT 0.4505 0.0920 0.5575 0.1040 ;
    END
  END A
  PIN Y
    DIRECTION OUTPUT ;
    USE SIGNAL ;
    PORT
      LAYER M0 ;
        RECT 0.0515 0.0160 0.4105 0.0280 ;
    END
  END Y
  PIN VDD
    DIRECTION INOUT ;
    USE POWER ;
    SHAPE ABUTMENT ;
    PORT
      LAYER BPR ;
        RECT 0.0000 0.1280 0.5880 0.1600 ;
    END
  END VDD
  PIN VSS
    DIRECTION INOUT ;
    USE GROUND ;
    SHAPE ABUTMENT ;
    PORT
      LAYER BPR ;
        RECT 0.0000 -0.0160 0.5880 0.0160 ;
    END
  END VSS
  OBS
    LAYER M0 ;
      RECT 0.0305 0.0400 0.5785 0.0520 ;
  END
END gt2_6t_buf_x10_w13_lvt

MACRO gt2_6t_buf_x12_w13_lvt
  CLASS CORE ;
  ORIGIN 0 0 ;
  FOREIGN gt2_6t_buf_x12_w13_lvt 0 0 ;
  SIZE 0.6720 BY 0.1440 ;
  SYMMETRY X Y ;
  SITE gt2_6t ;
  PIN A
    DIRECTION INPUT ;
    USE SIGNAL ;
    PORT
      LAYER M0 ;
        RECT 0.5345 0.0400 0.6415 0.0520 ;
    END
  END A
  PIN Y
    DIRECTION OUTPUT ;
    USE SIGNAL ;
    PORT
      LAYER M0 ;
        RECT 0.0515 0.0400 0.4945 0.0520 ;
    END
  END Y
  PIN VDD
    DIRECTION INOUT ;
    USE POWER ;
    SHAPE ABUTMENT ;
    PORT
      LAYER BPR ;
        RECT 0.0000 0.1280 0.6720 0.1600 ;
    END
  END VDD
  PIN VSS
    DIRECTION INOUT ;
    USE GROUND ;
    SHAPE ABUTMENT ;
    PORT
      LAYER BPR ;
        RECT 0.0000 -0.0160 0.6720 0.0160 ;
    END
  END VSS
  OBS
    LAYER M0 ;
      RECT 0.0305 0.0920 0.6625 0.1040 ;
  END
END gt2_6t_buf_x12_w13_lvt

MACRO gt2_6t_buf_x1_w13_lvt
  CLASS CORE ;
  ORIGIN 0 0 ;
  FOREIGN gt2_6t_buf_x1_w13_lvt 0 0 ;
  SIZE 0.1260 BY 0.1440 ;
  SYMMETRY X Y ;
  SITE gt2_6t ;
  PIN A
    DIRECTION INPUT ;
    USE SIGNAL ;
    PORT
      LAYER M0 ;
        RECT 0.0210 0.0920 0.0535 0.1040 ;
    END
  END A
  PIN Y
    DIRECTION OUTPUT ;
    USE SIGNAL ;
    PORT
      LAYER M0 ;
        RECT 0.0840 0.1160 0.1165 0.1280 ;
    END
  END Y
  PIN VDD
    DIRECTION INOUT ;
    USE POWER ;
    SHAPE ABUTMENT ;
    PORT
      LAYER BPR ;
        RECT 0.0000 0.1280 0.1260 0.1600 ;
    END
  END VDD
  PIN VSS
    DIRECTION INOUT ;
    USE GROUND ;
    SHAPE ABUTMENT ;
    PORT
      LAYER BPR ;
        RECT 0.0000 -0.0160 0.1260 0.0160 ;
    END
  END VSS
  OBS
    LAYER M0 ;
      RECT 0.0095 0.0160 0.0955 0.0280 ;
  END
END gt2_6t_buf_x1_w13_lvt

MACRO gt2_6t_buf_x2_w13_lvt
  CLASS CORE ;
  ORIGIN 0 0 ;
  FOREIGN gt2_6t_buf_x2_w13_lvt 0 0 ;
  SIZE 0.1680 BY 0.1440 ;
  SYMMETRY X Y ;
  SITE gt2_6t ;
  PIN A
    DIRECTION INPUT ;
    USE SIGNAL ;
    PORT
      LAYER M0 ;
        RECT 0.1145 0.0400 0.1470 0.0520 ;
    END
  END A
  PIN Y
    DIRECTION OUTPUT ;
    USE SIGNAL ;
    PORT
      LAYER M0 ;
        RECT 0.0515 0.0160 0.0840 0.0280 ;
    END
  END Y
  PIN VDD
    DIRECTION INOUT ;
    USE POWER ;
    SHAPE ABUTMENT ;
    PORT
      LAYER BPR ;
        RECT 0.0000 0.1280 0.1680 0.1600 ;
    END
  END VDD
  PIN VSS
    DIRECTION INOUT ;
    USE GROUND ;
    SHAPE ABUTMENT ;
    PORT
      LAYER BPR ;
        RECT 0.0000 -0.0160 0.1680 0.0160 ;
    END
  END VSS
  OBS
    LAYER M0 ;
      RECT 0.0305 0.1160 0.1585 0.1280 ;
  END
END gt2_6t_buf_x2_w13_lvt

MACRO gt2_6t_buf_x3_w13_lvt
  CLASS CORE ;
  ORIGIN 0 0 ;
  FOREIGN gt2_6t_buf_x3_w13_lvt 0 0 ;
  SIZE 0.2100 BY 0.1440 ;
  SYMMETRY X Y ;
  SITE gt2_6t ;
  PIN A
    DIRECTION INPUT ;
    USE SIGNAL ;
    PORT
      LAYER M0 ;
        RECT 0.0210 0.0920 0.0535 0.1040 ;
    END
  END A
  PIN Y
    DIRECTION OUTPUT ;
    USE SIGNAL ;
    PORT
      LAYER M0 ;
        RECT 0.0935 0.1160 0.2005 0.1280 ;
    END
  END Y
  PIN VDD
    DIRECTION INOUT ;
    USE POWER ;
    SHAPE ABUTMENT ;
    PORT
      LAYER BPR ;
        RECT 0.0000 0.1280 0.2100 0.1600 ;
    END
  END VDD
  PIN VSS
    DIRECTION INOUT ;
    USE GROUND ;
    SHAPE ABUTMENT ;
    PORT
      LAYER BPR ;
        RECT 0.0000 -0.0160 0.2100 0.0160 ;
    END
  END VSS
  OBS
    LAYER M0 ;
      RECT 0.0095 0.0400 0.1795 0.0520 ;
  END
END gt2_6t_buf_x3_w13_lvt

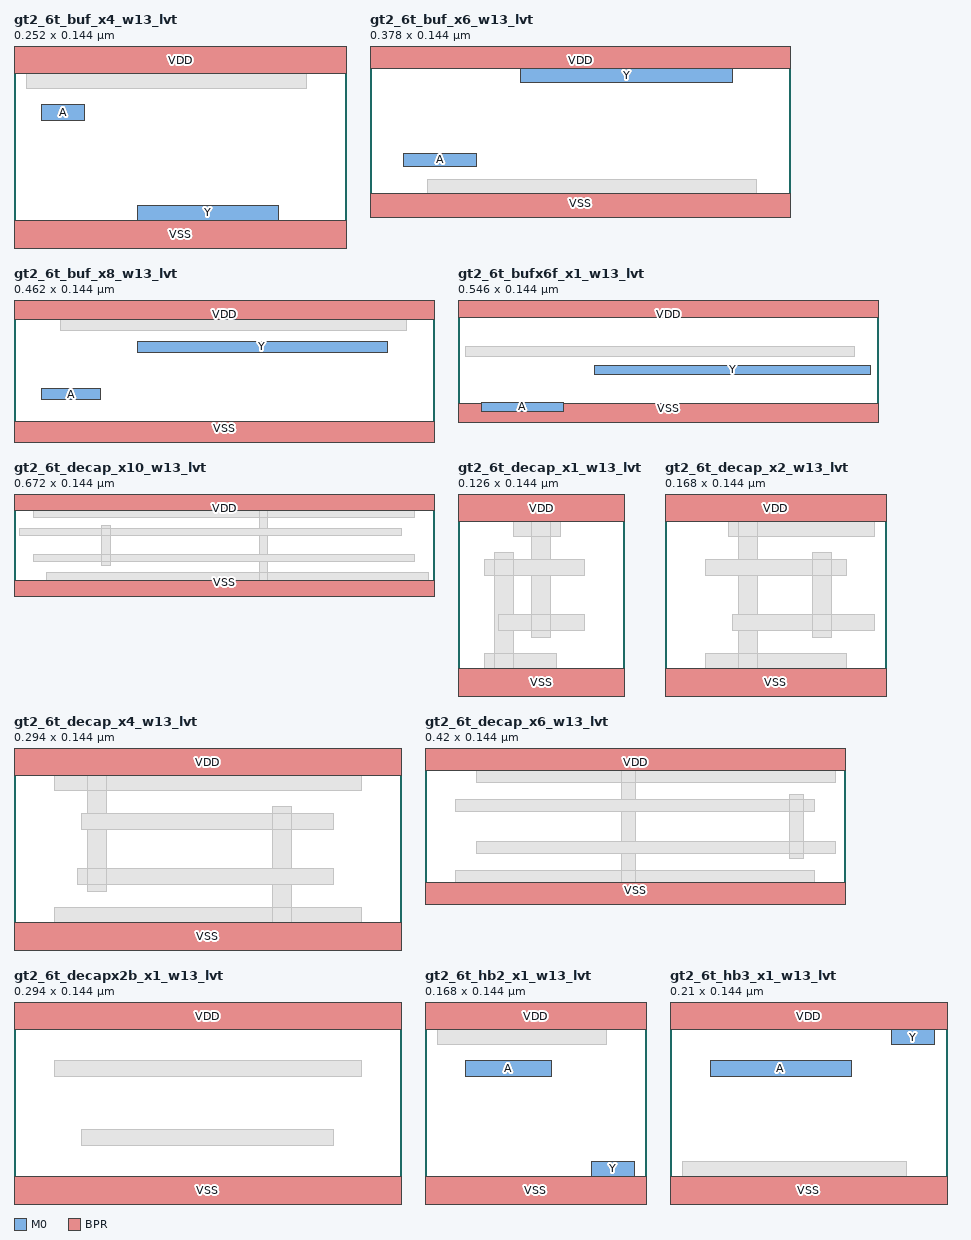
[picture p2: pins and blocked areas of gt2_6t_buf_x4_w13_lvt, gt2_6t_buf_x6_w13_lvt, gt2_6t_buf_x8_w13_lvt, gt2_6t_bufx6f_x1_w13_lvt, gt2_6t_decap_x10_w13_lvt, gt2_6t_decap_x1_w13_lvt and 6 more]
MACRO gt2_6t_buf_x4_w13_lvt
  CLASS CORE ;
  ORIGIN 0 0 ;
  FOREIGN gt2_6t_buf_x4_w13_lvt 0 0 ;
  SIZE 0.2520 BY 0.1440 ;
  SYMMETRY X Y ;
  SITE gt2_6t ;
  PIN A
    DIRECTION INPUT ;
    USE SIGNAL ;
    PORT
      LAYER M0 ;
        RECT 0.0210 0.0920 0.0535 0.1040 ;
    END
  END A
  PIN Y
    DIRECTION OUTPUT ;
    USE SIGNAL ;
    PORT
      LAYER M0 ;
        RECT 0.0935 0.0160 0.2005 0.0280 ;
    END
  END Y
  PIN VDD
    DIRECTION INOUT ;
    USE POWER ;
    SHAPE ABUTMENT ;
    PORT
      LAYER BPR ;
        RECT 0.0000 0.1280 0.2520 0.1600 ;
    END
  END VDD
  PIN VSS
    DIRECTION INOUT ;
    USE GROUND ;
    SHAPE ABUTMENT ;
    PORT
      LAYER BPR ;
        RECT 0.0000 -0.0160 0.2520 0.0160 ;
    END
  END VSS
  OBS
    LAYER M0 ;
      RECT 0.0095 0.1160 0.2215 0.1280 ;
  END
END gt2_6t_buf_x4_w13_lvt


MACRO gt2_6t_buf_x6_w13_lvt
  CLASS CORE ;
  ORIGIN 0 0 ;
  FOREIGN gt2_6t_buf_x6_w13_lvt 0 0 ;
  SIZE 0.3780 BY 0.1440 ;
  SYMMETRY X Y ;
  SITE gt2_6t ;
  PIN A
    DIRECTION INPUT ;
    USE SIGNAL ;
    PORT
      LAYER M0 ;
        RECT 0.0305 0.0400 0.0955 0.0520 ;
    END
  END A
  PIN Y
    DIRECTION OUTPUT ;
    USE SIGNAL ;
    PORT
      LAYER M0 ;
        RECT 0.1355 0.1160 0.3265 0.1280 ;
    END
  END Y
  PIN VDD
    DIRECTION INOUT ;
    USE POWER ;
    SHAPE ABUTMENT ;
    PORT
      LAYER BPR ;
        RECT 0.0000 0.1280 0.3780 0.1600 ;
    END
  END VDD
  PIN VSS
    DIRECTION INOUT ;
    USE GROUND ;
    SHAPE ABUTMENT ;
    PORT
      LAYER BPR ;
        RECT 0.0000 -0.0160 0.3780 0.0160 ;
    END
  END VSS
  OBS
    LAYER M0 ;
      RECT 0.0515 0.0160 0.3475 0.0280 ;
  END
END gt2_6t_buf_x6_w13_lvt

MACRO gt2_6t_buf_x8_w13_lvt
  CLASS CORE ;
  ORIGIN 0 0 ;
  FOREIGN gt2_6t_buf_x8_w13_lvt 0 0 ;
  SIZE 0.4620 BY 0.1440 ;
  SYMMETRY X Y ;
  SITE gt2_6t ;
  PIN A
    DIRECTION INPUT ;
    USE SIGNAL ;
    PORT
      LAYER M0 ;
        RECT 0.0305 0.0400 0.0955 0.0520 ;
    END
  END A
  PIN Y
    DIRECTION OUTPUT ;
    USE SIGNAL ;
    PORT
      LAYER M0 ;
        RECT 0.1355 0.0920 0.4105 0.1040 ;
    END
  END Y
  PIN VDD
    DIRECTION INOUT ;
    USE POWER ;
    SHAPE ABUTMENT ;
    PORT
      LAYER BPR ;
        RECT 0.0000 0.1280 0.4620 0.1600 ;
    END
  END VDD
  PIN VSS
    DIRECTION INOUT ;
    USE GROUND ;
    SHAPE ABUTMENT ;
    PORT
      LAYER BPR ;
        RECT 0.0000 -0.0160 0.4620 0.0160 ;
    END
  END VSS
  OBS
    LAYER M0 ;
      RECT 0.0515 0.1160 0.4315 0.1280 ;
  END
END gt2_6t_buf_x8_w13_lvt


MACRO gt2_6t_bufx6f_x1_w13_lvt
  CLASS CORE ;
  ORIGIN 0 0 ;
  FOREIGN gt2_6t_bufx6f_x1_w13_lvt 0 0 ;
  SIZE 0.5460 BY 0.1440 ;
  SYMMETRY X Y ;
  SITE gt2_6t ;
  PIN A
    DIRECTION INPUT ;
    USE SIGNAL ;
    PORT
      LAYER M0 ;
        RECT 0.0305 0.0060 0.1375 0.0180 ;
    END
  END A
  PIN Y
    DIRECTION OUTPUT ;
    USE SIGNAL ;
    PORT
      LAYER M0 ;
        RECT 0.1775 0.0540 0.5365 0.0660 ;
    END
  END Y
  PIN VDD
    DIRECTION INOUT ;
    USE POWER ;
    SHAPE ABUTMENT ;
    PORT
      LAYER BPR ;
        RECT 0.0000 0.1280 0.5460 0.1600 ;
    END
  END VDD
  PIN VSS
    DIRECTION INOUT ;
    USE GROUND ;
    SHAPE ABUTMENT ;
    PORT
      LAYER BPR ;
        RECT 0.0000 -0.0160 0.5460 0.0160 ;
    END
  END VSS
  OBS
    LAYER M0 ;
      RECT 0.0095 0.0780 0.5155 0.0900 ;
  END
END gt2_6t_bufx6f_x1_w13_lvt

MACRO gt2_6t_decap_x10_w13_lvt
  CLASS CORE ;
  ORIGIN 0 0 ;
  FOREIGN gt2_6t_decap_x10_w13_lvt 0 0 ;
  SIZE 0.6720 BY 0.1440 ;
  SYMMETRY X Y ;
  SITE gt2_6t ;
  PIN VDD
    DIRECTION INOUT ;
    USE POWER ;
    SHAPE ABUTMENT ;
    PORT
      LAYER BPR ;
        RECT 0.0000 0.1280 0.6720 0.1600 ;
    END
  END VDD
  PIN VSS
    DIRECTION INOUT ;
    USE GROUND ;
    SHAPE ABUTMENT ;
    PORT
      LAYER BPR ;
        RECT 0.0000 -0.0160 0.6720 0.0160 ;
    END
  END VSS
  OBS
    LAYER M1 ;
      RECT 0.1400 0.0400 0.1540 0.1040 ;
      RECT 0.3920 0.0110 0.4060 0.1330 ;
    LAYER M0 ;
      RECT 0.0305 0.0450 0.6415 0.0570 ;
      RECT 0.0095 0.0870 0.6205 0.0990 ;
      RECT 0.0515 0.0160 0.6625 0.0280 ;
      RECT 0.0305 0.1160 0.6415 0.1280 ;
    LAYER V0 ;
      RECT 0.1400 0.0450 0.1540 0.0570 ;
      RECT 0.1400 0.0870 0.1540 0.0990 ;
      RECT 0.3920 0.0160 0.4060 0.0280 ;
      RECT 0.3920 0.1160 0.4060 0.1280 ;
  END
END gt2_6t_decap_x10_w13_lvt

MACRO gt2_6t_decap_x1_w13_lvt
  CLASS CORE ;
  ORIGIN 0 0 ;
  FOREIGN gt2_6t_decap_x1_w13_lvt 0 0 ;
  SIZE 0.1260 BY 0.1440 ;
  SYMMETRY X Y ;
  SITE gt2_6t ;
  PIN VDD
    DIRECTION INOUT ;
    USE POWER ;
    SHAPE ABUTMENT ;
    PORT
      LAYER BPR ;
        RECT 0.0000 0.1280 0.1260 0.1600 ;
    END
  END VDD
  PIN VSS
    DIRECTION INOUT ;
    USE GROUND ;
    SHAPE ABUTMENT ;
    PORT
      LAYER BPR ;
        RECT 0.0000 -0.0160 0.1260 0.0160 ;
    END
  END VSS
  OBS
    LAYER M1 ;
      RECT 0.0560 0.0400 0.0700 0.1330 ;
      RECT 0.0280 0.0110 0.0420 0.1040 ;
    LAYER M0 ;
      RECT 0.0305 0.0450 0.0955 0.0570 ;
      RECT 0.0420 0.1160 0.0780 0.1280 ;
      RECT 0.0200 0.0160 0.0745 0.0280 ;
      RECT 0.0200 0.0870 0.0955 0.0990 ;
    LAYER V0 ;
      RECT 0.0560 0.0450 0.0700 0.0570 ;
      RECT 0.0560 0.1160 0.0700 0.1280 ;
      RECT 0.0280 0.0160 0.0420 0.0280 ;
      RECT 0.0280 0.0870 0.0420 0.0990 ;
  END
END gt2_6t_decap_x1_w13_lvt

MACRO gt2_6t_decap_x2_w13_lvt
  CLASS CORE ;
  ORIGIN 0 0 ;
  FOREIGN gt2_6t_decap_x2_w13_lvt 0 0 ;
  SIZE 0.1680 BY 0.1440 ;
  SYMMETRY X Y ;
  SITE gt2_6t ;
  PIN VDD
    DIRECTION INOUT ;
    USE POWER ;
    SHAPE ABUTMENT ;
    PORT
      LAYER BPR ;
        RECT 0.0000 0.1280 0.1680 0.1600 ;
    END
  END VDD
  PIN VSS
    DIRECTION INOUT ;
    USE GROUND ;
    SHAPE ABUTMENT ;
    PORT
      LAYER BPR ;
        RECT 0.0000 -0.0160 0.1680 0.0160 ;
    END
  END VSS
  OBS
    LAYER M1 ;
      RECT 0.0560 0.0110 0.0700 0.1330 ;
      RECT 0.1120 0.0400 0.1260 0.1040 ;
    LAYER M0 ;
      RECT 0.0305 0.0160 0.1375 0.0280 ;
      RECT 0.0480 0.1160 0.1585 0.1280 ;
      RECT 0.0515 0.0450 0.1585 0.0570 ;
      RECT 0.0305 0.0870 0.1375 0.0990 ;
    LAYER V0 ;
      RECT 0.0560 0.0160 0.0700 0.0280 ;
      RECT 0.0560 0.1160 0.0700 0.1280 ;
      RECT 0.1120 0.0450 0.1260 0.0570 ;
      RECT 0.1120 0.0870 0.1260 0.0990 ;
  END
END gt2_6t_decap_x2_w13_lvt

MACRO gt2_6t_decap_x4_w13_lvt
  CLASS CORE ;
  ORIGIN 0 0 ;
  FOREIGN gt2_6t_decap_x4_w13_lvt 0 0 ;
  SIZE 0.2940 BY 0.1440 ;
  SYMMETRY X Y ;
  SITE gt2_6t ;
  PIN VDD
    DIRECTION INOUT ;
    USE POWER ;
    SHAPE ABUTMENT ;
    PORT
      LAYER BPR ;
        RECT 0.0000 0.1280 0.2940 0.1600 ;
    END
  END VDD
  PIN VSS
    DIRECTION INOUT ;
    USE GROUND ;
    SHAPE ABUTMENT ;
    PORT
      LAYER BPR ;
        RECT 0.0000 -0.0160 0.2940 0.0160 ;
    END
  END VSS
  OBS
    LAYER M1 ;
      RECT 0.0560 0.0400 0.0700 0.1330 ;
      RECT 0.1960 0.0110 0.2100 0.1040 ;
    LAYER M0 ;
      RECT 0.0480 0.0450 0.2425 0.0570 ;
      RECT 0.0305 0.1160 0.2635 0.1280 ;
      RECT 0.0305 0.0160 0.2635 0.0280 ;
      RECT 0.0515 0.0870 0.2425 0.0990 ;
    LAYER V0 ;
      RECT 0.0560 0.0450 0.0700 0.0570 ;
      RECT 0.0560 0.1160 0.0700 0.1280 ;
      RECT 0.1960 0.0160 0.2100 0.0280 ;
      RECT 0.1960 0.0870 0.2100 0.0990 ;
  END
END gt2_6t_decap_x4_w13_lvt

MACRO gt2_6t_decap_x6_w13_lvt
  CLASS CORE ;
  ORIGIN 0 0 ;
  FOREIGN gt2_6t_decap_x6_w13_lvt 0 0 ;
  SIZE 0.4200 BY 0.1440 ;
  SYMMETRY X Y ;
  SITE gt2_6t ;
  PIN VDD
    DIRECTION INOUT ;
    USE POWER ;
    SHAPE ABUTMENT ;
    PORT
      LAYER BPR ;
        RECT 0.0000 0.1280 0.4200 0.1600 ;
    END
  END VDD
  PIN VSS
    DIRECTION INOUT ;
    USE GROUND ;
    SHAPE ABUTMENT ;
    PORT
      LAYER BPR ;
        RECT 0.0000 -0.0160 0.4200 0.0160 ;
    END
  END VSS
  OBS
    LAYER M1 ;
      RECT 0.1960 0.0110 0.2100 0.1330 ;
      RECT 0.3640 0.0400 0.3780 0.1040 ;
    LAYER M0 ;
      RECT 0.0305 0.0160 0.3895 0.0280 ;
      RECT 0.0515 0.1160 0.4105 0.1280 ;
      RECT 0.0515 0.0450 0.4105 0.0570 ;
      RECT 0.0305 0.0870 0.3895 0.0990 ;
    LAYER V0 ;
      RECT 0.1960 0.0160 0.2100 0.0280 ;
      RECT 0.1960 0.1160 0.2100 0.1280 ;
      RECT 0.3640 0.0450 0.3780 0.0570 ;
      RECT 0.3640 0.0870 0.3780 0.0990 ;
  END
END gt2_6t_decap_x6_w13_lvt

MACRO gt2_6t_decapx2b_x1_w13_lvt
  CLASS CORE ;
  ORIGIN 0 0 ;
  FOREIGN gt2_6t_decapx2b_x1_w13_lvt 0 0 ;
  SIZE 0.2940 BY 0.1440 ;
  SYMMETRY X Y ;
  SITE gt2_6t ;
  PIN VDD
    DIRECTION INOUT ;
    USE POWER ;
    SHAPE ABUTMENT ;
    PORT
      LAYER BPR ;
        RECT 0.0000 0.1280 0.2940 0.1600 ;
    END
  END VDD
  PIN VSS
    DIRECTION INOUT ;
    USE GROUND ;
    SHAPE ABUTMENT ;
    PORT
      LAYER BPR ;
        RECT 0.0000 -0.0160 0.2940 0.0160 ;
    END
  END VSS
  OBS
    LAYER M0 ;
      RECT 0.0515 0.0400 0.2425 0.0520 ;
      RECT 0.0305 0.0920 0.2635 0.1040 ;
  END
END gt2_6t_decapx2b_x1_w13_lvt


MACRO gt2_6t_hb2_x1_w13_lvt
  CLASS CORE ;
  ORIGIN 0 0 ;
  FOREIGN gt2_6t_hb2_x1_w13_lvt 0 0 ;
  SIZE 0.1680 BY 0.1440 ;
  SYMMETRY X Y ;
  SITE gt2_6t ;
  PIN A
    DIRECTION INPUT ;
    USE SIGNAL ;
    PORT
      LAYER M0 ;
        RECT 0.0305 0.0920 0.0955 0.1040 ;
    END
  END A
  PIN Y
    DIRECTION OUTPUT ;
    USE SIGNAL ;
    PORT
      LAYER M0 ;
        RECT 0.1260 0.0160 0.1585 0.0280 ;
    END
  END Y
  PIN VDD
    DIRECTION INOUT ;
    USE POWER ;
    SHAPE ABUTMENT ;
    PORT
      LAYER BPR ;
        RECT 0.0000 0.1280 0.1680 0.1600 ;
    END
  END VDD
  PIN VSS
    DIRECTION INOUT ;
    USE GROUND ;
    SHAPE ABUTMENT ;
    PORT
      LAYER BPR ;
        RECT 0.0000 -0.0160 0.1680 0.0160 ;
    END
  END VSS
  OBS
    LAYER M0 ;
      RECT 0.0095 0.1160 0.1375 0.1280 ;
  END
END gt2_6t_hb2_x1_w13_lvt

MACRO gt2_6t_hb3_x1_w13_lvt
  CLASS CORE ;
  ORIGIN 0 0 ;
  FOREIGN gt2_6t_hb3_x1_w13_lvt 0 0 ;
  SIZE 0.2100 BY 0.1440 ;
  SYMMETRY X Y ;
  SITE gt2_6t ;
  PIN A
    DIRECTION INPUT ;
    USE SIGNAL ;
    PORT
      LAYER M0 ;
        RECT 0.0305 0.0920 0.1375 0.1040 ;
    END
  END A
  PIN Y
    DIRECTION OUTPUT ;
    USE SIGNAL ;
    PORT
      LAYER M0 ;
        RECT 0.1680 0.1160 0.2005 0.1280 ;
    END
  END Y
  PIN VDD
    DIRECTION INOUT ;
    USE POWER ;
    SHAPE ABUTMENT ;
    PORT
      LAYER BPR ;
        RECT 0.0000 0.1280 0.2100 0.1600 ;
    END
  END VDD
  PIN VSS
    DIRECTION INOUT ;
    USE GROUND ;
    SHAPE ABUTMENT ;
    PORT
      LAYER BPR ;
        RECT 0.0000 -0.0160 0.2100 0.0160 ;
    END
  END VSS
  OBS
    LAYER M0 ;
      RECT 0.0095 0.0160 0.1795 0.0280 ;
  END
END gt2_6t_hb3_x1_w13_lvt

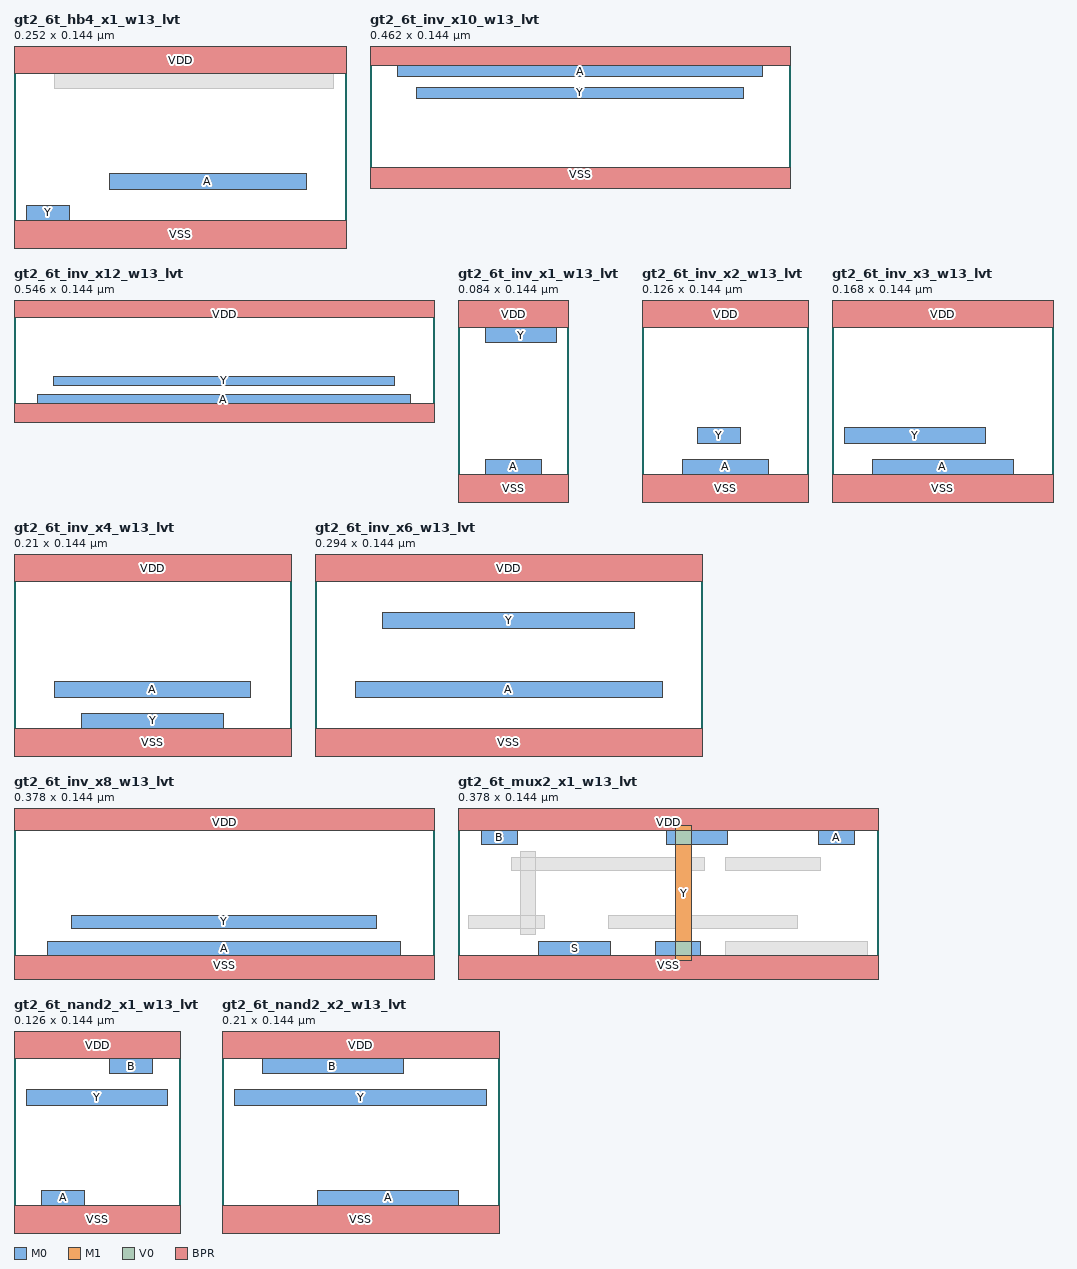
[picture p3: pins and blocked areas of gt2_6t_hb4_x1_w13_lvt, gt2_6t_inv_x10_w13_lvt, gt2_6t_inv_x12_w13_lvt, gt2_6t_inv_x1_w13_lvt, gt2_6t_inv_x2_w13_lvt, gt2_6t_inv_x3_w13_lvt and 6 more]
MACRO gt2_6t_hb4_x1_w13_lvt
  CLASS CORE ;
  ORIGIN 0 0 ;
  FOREIGN gt2_6t_hb4_x1_w13_lvt 0 0 ;
  SIZE 0.2520 BY 0.1440 ;
  SYMMETRY X Y ;
  SITE gt2_6t ;
  PIN A
    DIRECTION INPUT ;
    USE SIGNAL ;
    PORT
      LAYER M0 ;
        RECT 0.0725 0.0400 0.2215 0.0520 ;
    END
  END A
  PIN Y
    DIRECTION OUTPUT ;
    USE SIGNAL ;
    PORT
      LAYER M0 ;
        RECT 0.0095 0.0160 0.0420 0.0280 ;
    END
  END Y
  PIN VDD
    DIRECTION INOUT ;
    USE POWER ;
    SHAPE ABUTMENT ;
    PORT
      LAYER BPR ;
        RECT 0.0000 0.1280 0.2520 0.1600 ;
    END
  END VDD
  PIN VSS
    DIRECTION INOUT ;
    USE GROUND ;
    SHAPE ABUTMENT ;
    PORT
      LAYER BPR ;
        RECT 0.0000 -0.0160 0.2520 0.0160 ;
    END
  END VSS
  OBS
    LAYER M0 ;
      RECT 0.0305 0.1160 0.2425 0.1280 ;
  END
END gt2_6t_hb4_x1_w13_lvt

MACRO gt2_6t_inv_x10_w13_lvt
  CLASS CORE ;
  ORIGIN 0 0 ;
  FOREIGN gt2_6t_inv_x10_w13_lvt 0 0 ;
  SIZE 0.4620 BY 0.1440 ;
  SYMMETRY X Y ;
  SITE gt2_6t ;
  PIN A
    DIRECTION INPUT ;
    USE SIGNAL ;
    PORT
      LAYER M0 ;
        RECT 0.0305 0.1160 0.4315 0.1280 ;
    END
  END A
  PIN Y
    DIRECTION OUTPUT ;
    USE SIGNAL ;
    PORT
      LAYER M0 ;
        RECT 0.0515 0.0920 0.4105 0.1040 ;
    END
  END Y
  PIN VDD
    DIRECTION INOUT ;
    USE POWER ;
    SHAPE ABUTMENT ;
    PORT
      LAYER BPR ;
        RECT 0.0000 0.1280 0.4620 0.1600 ;
    END
  END VDD
  PIN VSS
    DIRECTION INOUT ;
    USE GROUND ;
    SHAPE ABUTMENT ;
    PORT
      LAYER BPR ;
        RECT 0.0000 -0.0160 0.4620 0.0160 ;
    END
  END VSS
END gt2_6t_inv_x10_w13_lvt

MACRO gt2_6t_inv_x12_w13_lvt
  CLASS CORE ;
  ORIGIN 0 0 ;
  FOREIGN gt2_6t_inv_x12_w13_lvt 0 0 ;
  SIZE 0.5460 BY 0.1440 ;
  SYMMETRY X Y ;
  SITE gt2_6t ;
  PIN A
    DIRECTION INPUT ;
    USE SIGNAL ;
    PORT
      LAYER M0 ;
        RECT 0.0305 0.0160 0.5155 0.0280 ;
    END
  END A
  PIN Y
    DIRECTION OUTPUT ;
    USE SIGNAL ;
    PORT
      LAYER M0 ;
        RECT 0.0515 0.0400 0.4945 0.0520 ;
    END
  END Y
  PIN VDD
    DIRECTION INOUT ;
    USE POWER ;
    SHAPE ABUTMENT ;
    PORT
      LAYER BPR ;
        RECT 0.0000 0.1280 0.5460 0.1600 ;
    END
  END VDD
  PIN VSS
    DIRECTION INOUT ;
    USE GROUND ;
    SHAPE ABUTMENT ;
    PORT
      LAYER BPR ;
        RECT 0.0000 -0.0160 0.5460 0.0160 ;
    END
  END VSS
END gt2_6t_inv_x12_w13_lvt

MACRO gt2_6t_inv_x1_w13_lvt
  CLASS CORE ;
  ORIGIN 0 0 ;
  FOREIGN gt2_6t_inv_x1_w13_lvt 0 0 ;
  SIZE 0.0840 BY 0.1440 ;
  SYMMETRY X Y ;
  SITE gt2_6t ;
  PIN A
    DIRECTION INPUT ;
    USE SIGNAL ;
    PORT
      LAYER M0 ;
        RECT 0.0210 0.0160 0.0630 0.0280 ;
    END
  END A
  PIN Y
    DIRECTION OUTPUT ;
    USE SIGNAL ;
    PORT
      LAYER M0 ;
        RECT 0.0210 0.1160 0.0745 0.1280 ;
    END
  END Y
  PIN VDD
    DIRECTION INOUT ;
    USE POWER ;
    SHAPE ABUTMENT ;
    PORT
      LAYER BPR ;
        RECT 0.0000 0.1280 0.0840 0.1600 ;
    END
  END VDD
  PIN VSS
    DIRECTION INOUT ;
    USE GROUND ;
    SHAPE ABUTMENT ;
    PORT
      LAYER BPR ;
        RECT 0.0000 -0.0160 0.0840 0.0160 ;
    END
  END VSS
END gt2_6t_inv_x1_w13_lvt

MACRO gt2_6t_inv_x2_w13_lvt
  CLASS CORE ;
  ORIGIN 0 0 ;
  FOREIGN gt2_6t_inv_x2_w13_lvt 0 0 ;
  SIZE 0.1260 BY 0.1440 ;
  SYMMETRY X Y ;
  SITE gt2_6t ;
  PIN A
    DIRECTION INPUT ;
    USE SIGNAL ;
    PORT
      LAYER M0 ;
        RECT 0.0305 0.0160 0.0955 0.0280 ;
    END
  END A
  PIN Y
    DIRECTION OUTPUT ;
    USE SIGNAL ;
    PORT
      LAYER M0 ;
        RECT 0.0420 0.0400 0.0745 0.0520 ;
    END
  END Y
  PIN VDD
    DIRECTION INOUT ;
    USE POWER ;
    SHAPE ABUTMENT ;
    PORT
      LAYER BPR ;
        RECT 0.0000 0.1280 0.1260 0.1600 ;
    END
  END VDD
  PIN VSS
    DIRECTION INOUT ;
    USE GROUND ;
    SHAPE ABUTMENT ;
    PORT
      LAYER BPR ;
        RECT 0.0000 -0.0160 0.1260 0.0160 ;
    END
  END VSS
END gt2_6t_inv_x2_w13_lvt

MACRO gt2_6t_inv_x3_w13_lvt
  CLASS CORE ;
  ORIGIN 0 0 ;
  FOREIGN gt2_6t_inv_x3_w13_lvt 0 0 ;
  SIZE 0.1680 BY 0.1440 ;
  SYMMETRY X Y ;
  SITE gt2_6t ;
  PIN A
    DIRECTION INPUT ;
    USE SIGNAL ;
    PORT
      LAYER M0 ;
        RECT 0.0305 0.0160 0.1375 0.0280 ;
    END
  END A
  PIN Y
    DIRECTION OUTPUT ;
    USE SIGNAL ;
    PORT
      LAYER M0 ;
        RECT 0.0095 0.0400 0.1165 0.0520 ;
    END
  END Y
  PIN VDD
    DIRECTION INOUT ;
    USE POWER ;
    SHAPE ABUTMENT ;
    PORT
      LAYER BPR ;
        RECT 0.0000 0.1280 0.1680 0.1600 ;
    END
  END VDD
  PIN VSS
    DIRECTION INOUT ;
    USE GROUND ;
    SHAPE ABUTMENT ;
    PORT
      LAYER BPR ;
        RECT 0.0000 -0.0160 0.1680 0.0160 ;
    END
  END VSS
END gt2_6t_inv_x3_w13_lvt

MACRO gt2_6t_inv_x4_w13_lvt
  CLASS CORE ;
  ORIGIN 0 0 ;
  FOREIGN gt2_6t_inv_x4_w13_lvt 0 0 ;
  SIZE 0.2100 BY 0.1440 ;
  SYMMETRY X Y ;
  SITE gt2_6t ;
  PIN A
    DIRECTION INPUT ;
    USE SIGNAL ;
    PORT
      LAYER M0 ;
        RECT 0.0305 0.0400 0.1795 0.0520 ;
    END
  END A
  PIN Y
    DIRECTION OUTPUT ;
    USE SIGNAL ;
    PORT
      LAYER M0 ;
        RECT 0.0515 0.0160 0.1585 0.0280 ;
    END
  END Y
  PIN VDD
    DIRECTION INOUT ;
    USE POWER ;
    SHAPE ABUTMENT ;
    PORT
      LAYER BPR ;
        RECT 0.0000 0.1280 0.2100 0.1600 ;
    END
  END VDD
  PIN VSS
    DIRECTION INOUT ;
    USE GROUND ;
    SHAPE ABUTMENT ;
    PORT
      LAYER BPR ;
        RECT 0.0000 -0.0160 0.2100 0.0160 ;
    END
  END VSS
END gt2_6t_inv_x4_w13_lvt


MACRO gt2_6t_inv_x6_w13_lvt
  CLASS CORE ;
  ORIGIN 0 0 ;
  FOREIGN gt2_6t_inv_x6_w13_lvt 0 0 ;
  SIZE 0.2940 BY 0.1440 ;
  SYMMETRY X Y ;
  SITE gt2_6t ;
  PIN A
    DIRECTION INPUT ;
    USE SIGNAL ;
    PORT
      LAYER M0 ;
        RECT 0.0305 0.0400 0.2635 0.0520 ;
    END
  END A
  PIN Y
    DIRECTION OUTPUT ;
    USE SIGNAL ;
    PORT
      LAYER M0 ;
        RECT 0.0515 0.0920 0.2425 0.1040 ;
    END
  END Y
  PIN VDD
    DIRECTION INOUT ;
    USE POWER ;
    SHAPE ABUTMENT ;
    PORT
      LAYER BPR ;
        RECT 0.0000 0.1280 0.2940 0.1600 ;
    END
  END VDD
  PIN VSS
    DIRECTION INOUT ;
    USE GROUND ;
    SHAPE ABUTMENT ;
    PORT
      LAYER BPR ;
        RECT 0.0000 -0.0160 0.2940 0.0160 ;
    END
  END VSS
END gt2_6t_inv_x6_w13_lvt

MACRO gt2_6t_inv_x8_w13_lvt
  CLASS CORE ;
  ORIGIN 0 0 ;
  FOREIGN gt2_6t_inv_x8_w13_lvt 0 0 ;
  SIZE 0.3780 BY 0.1440 ;
  SYMMETRY X Y ;
  SITE gt2_6t ;
  PIN A
    DIRECTION INPUT ;
    USE SIGNAL ;
    PORT
      LAYER M0 ;
        RECT 0.0305 0.0160 0.3475 0.0280 ;
    END
  END A
  PIN Y
    DIRECTION OUTPUT ;
    USE SIGNAL ;
    PORT
      LAYER M0 ;
        RECT 0.0515 0.0400 0.3265 0.0520 ;
    END
  END Y
  PIN VDD
    DIRECTION INOUT ;
    USE POWER ;
    SHAPE ABUTMENT ;
    PORT
      LAYER BPR ;
        RECT 0.0000 0.1280 0.3780 0.1600 ;
    END
  END VDD
  PIN VSS
    DIRECTION INOUT ;
    USE GROUND ;
    SHAPE ABUTMENT ;
    PORT
      LAYER BPR ;
        RECT 0.0000 -0.0160 0.3780 0.0160 ;
    END
  END VSS
END gt2_6t_inv_x8_w13_lvt


MACRO gt2_6t_mux2_x1_w13_lvt
  CLASS CORE ;
  ORIGIN 0 0 ;
  FOREIGN gt2_6t_mux2_x1_w13_lvt 0 0 ;
  SIZE 0.3780 BY 0.1440 ;
  SYMMETRY X Y ;
  SITE gt2_6t ;
  PIN A
    DIRECTION INPUT ;
    USE SIGNAL ;
    PORT
      LAYER M0 ;
        RECT 0.3245 0.1160 0.3570 0.1280 ;
    END
  END A
  PIN B
    DIRECTION INPUT ;
    USE SIGNAL ;
    PORT
      LAYER M0 ;
        RECT 0.0210 0.1160 0.0535 0.1280 ;
    END
  END B
  PIN S
    DIRECTION INPUT ;
    USE SIGNAL ;
    PORT
      LAYER M0 ;
        RECT 0.0725 0.0160 0.1375 0.0280 ;
    END
  END S
  PIN Y
    DIRECTION OUTPUT ;
    USE SIGNAL ;
    PORT
      LAYER M1 ;
        RECT 0.1960 0.0110 0.2100 0.1330 ;
      LAYER M0 ;
        RECT 0.1775 0.0160 0.2180 0.0280 ;
        RECT 0.1880 0.1160 0.2425 0.1280 ;
      LAYER V0 ;
        RECT 0.1960 0.0160 0.2100 0.0280 ;
        RECT 0.1960 0.1160 0.2100 0.1280 ;
    END
  END Y
  PIN VDD
    DIRECTION INOUT ;
    USE POWER ;
    SHAPE ABUTMENT ;
    PORT
      LAYER BPR ;
        RECT 0.0000 0.1280 0.3780 0.1600 ;
    END
  END VDD
  PIN VSS
    DIRECTION INOUT ;
    USE GROUND ;
    SHAPE ABUTMENT ;
    PORT
      LAYER BPR ;
        RECT 0.0000 -0.0160 0.3780 0.0160 ;
    END
  END VSS
  OBS
    LAYER M1 ;
      RECT 0.0560 0.0350 0.0700 0.1090 ;
    LAYER M0 ;
      RECT 0.2405 0.0160 0.3685 0.0280 ;
      RECT 0.2405 0.0920 0.3265 0.1040 ;
      RECT 0.0095 0.0400 0.0780 0.0520 ;
      RECT 0.0480 0.0920 0.2215 0.1040 ;
      RECT 0.1355 0.0400 0.3055 0.0520 ;
    LAYER V0 ;
      RECT 0.0560 0.0400 0.0700 0.0520 ;
      RECT 0.0560 0.0920 0.0700 0.1040 ;
  END
END gt2_6t_mux2_x1_w13_lvt

MACRO gt2_6t_nand2_x1_w13_lvt
  CLASS CORE ;
  ORIGIN 0 0 ;
  FOREIGN gt2_6t_nand2_x1_w13_lvt 0 0 ;
  SIZE 0.1260 BY 0.1440 ;
  SYMMETRY X Y ;
  SITE gt2_6t ;
  PIN A
    DIRECTION INPUT ;
    USE SIGNAL ;
    PORT
      LAYER M0 ;
        RECT 0.0210 0.0160 0.0535 0.0280 ;
    END
  END A
  PIN B
    DIRECTION INPUT ;
    USE SIGNAL ;
    PORT
      LAYER M0 ;
        RECT 0.0725 0.1160 0.1050 0.1280 ;
    END
  END B
  PIN Y
    DIRECTION OUTPUT ;
    USE SIGNAL ;
    PORT
      LAYER M0 ;
        RECT 0.0095 0.0920 0.1165 0.1040 ;
    END
  END Y
  PIN VDD
    DIRECTION INOUT ;
    USE POWER ;
    SHAPE ABUTMENT ;
    PORT
      LAYER BPR ;
        RECT 0.0000 0.1280 0.1260 0.1600 ;
    END
  END VDD
  PIN VSS
    DIRECTION INOUT ;
    USE GROUND ;
    SHAPE ABUTMENT ;
    PORT
      LAYER BPR ;
        RECT 0.0000 -0.0160 0.1260 0.0160 ;
    END
  END VSS
END gt2_6t_nand2_x1_w13_lvt

MACRO gt2_6t_nand2_x2_w13_lvt
  CLASS CORE ;
  ORIGIN 0 0 ;
  FOREIGN gt2_6t_nand2_x2_w13_lvt 0 0 ;
  SIZE 0.2100 BY 0.1440 ;
  SYMMETRY X Y ;
  SITE gt2_6t ;
  PIN A
    DIRECTION INPUT ;
    USE SIGNAL ;
    PORT
      LAYER M0 ;
        RECT 0.0725 0.0160 0.1795 0.0280 ;
    END
  END A
  PIN B
    DIRECTION INPUT ;
    USE SIGNAL ;
    PORT
      LAYER M0 ;
        RECT 0.0305 0.1160 0.1375 0.1280 ;
    END
  END B
  PIN Y
    DIRECTION OUTPUT ;
    USE SIGNAL ;
    PORT
      LAYER M0 ;
        RECT 0.0095 0.0920 0.2005 0.1040 ;
    END
  END Y
  PIN VDD
    DIRECTION INOUT ;
    USE POWER ;
    SHAPE ABUTMENT ;
    PORT
      LAYER BPR ;
        RECT 0.0000 0.1280 0.2100 0.1600 ;
    END
  END VDD
  PIN VSS
    DIRECTION INOUT ;
    USE GROUND ;
    SHAPE ABUTMENT ;
    PORT
      LAYER BPR ;
        RECT 0.0000 -0.0160 0.2100 0.0160 ;
    END
  END VSS
END gt2_6t_nand2_x2_w13_lvt

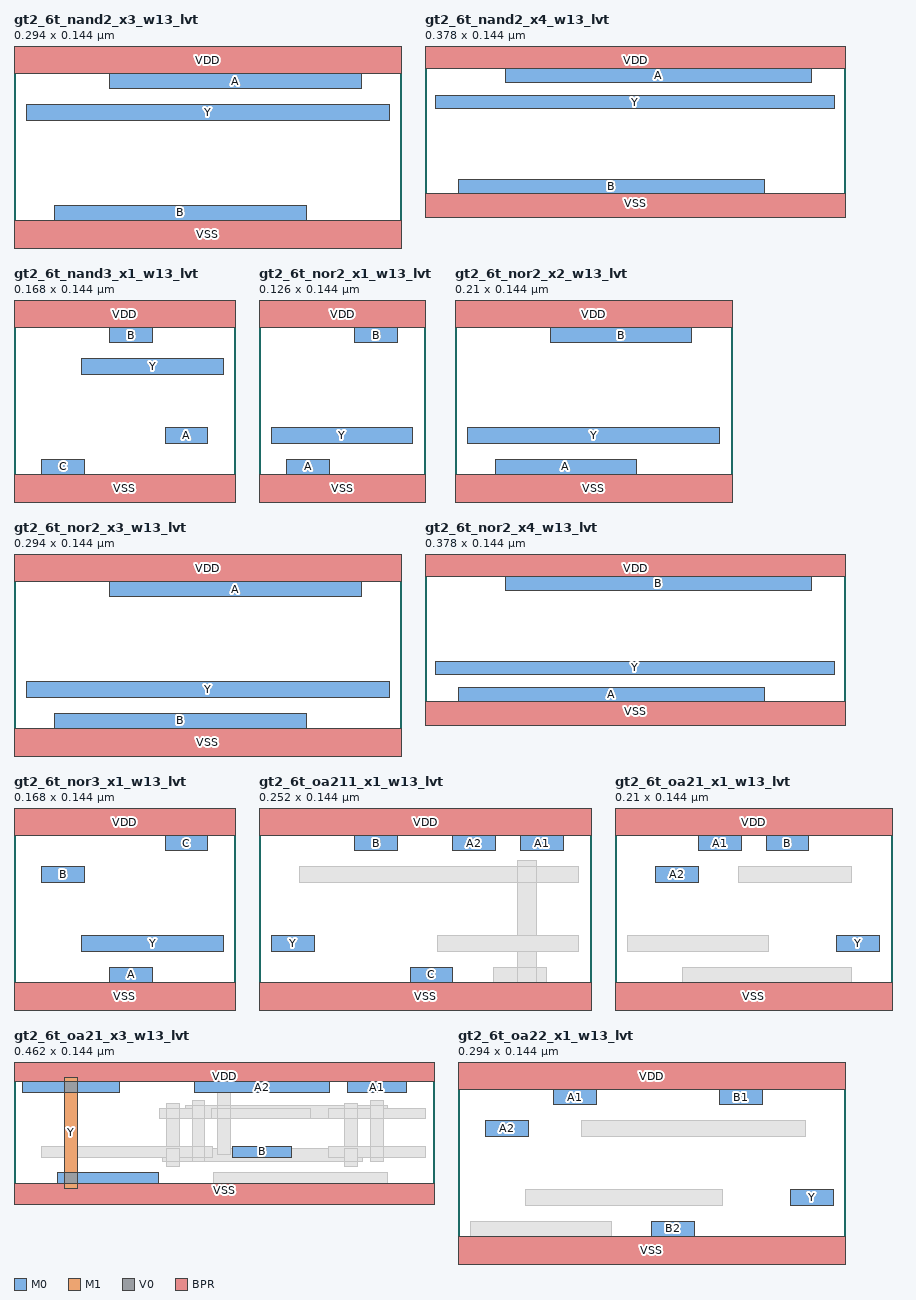
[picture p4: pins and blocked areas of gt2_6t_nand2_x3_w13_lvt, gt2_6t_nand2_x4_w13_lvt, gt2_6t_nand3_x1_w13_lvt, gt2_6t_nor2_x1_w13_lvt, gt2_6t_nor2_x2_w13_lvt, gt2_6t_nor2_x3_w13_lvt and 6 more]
MACRO gt2_6t_nand2_x3_w13_lvt
  CLASS CORE ;
  ORIGIN 0 0 ;
  FOREIGN gt2_6t_nand2_x3_w13_lvt 0 0 ;
  SIZE 0.2940 BY 0.1440 ;
  SYMMETRY X Y ;
  SITE gt2_6t ;
  PIN A
    DIRECTION INPUT ;
    USE SIGNAL ;
    PORT
      LAYER M0 ;
        RECT 0.0725 0.1160 0.2635 0.1280 ;
    END
  END A
  PIN B
    DIRECTION INPUT ;
    USE SIGNAL ;
    PORT
      LAYER M0 ;
        RECT 0.0305 0.0160 0.2215 0.0280 ;
    END
  END B
  PIN Y
    DIRECTION OUTPUT ;
    USE SIGNAL ;
    PORT
      LAYER M0 ;
        RECT 0.0095 0.0920 0.2845 0.1040 ;
    END
  END Y
  PIN VDD
    DIRECTION INOUT ;
    USE POWER ;
    SHAPE ABUTMENT ;
    PORT
      LAYER BPR ;
        RECT 0.0000 0.1280 0.2940 0.1600 ;
    END
  END VDD
  PIN VSS
    DIRECTION INOUT ;
    USE GROUND ;
    SHAPE ABUTMENT ;
    PORT
      LAYER BPR ;
        RECT 0.0000 -0.0160 0.2940 0.0160 ;
    END
  END VSS
END gt2_6t_nand2_x3_w13_lvt

MACRO gt2_6t_nand2_x4_w13_lvt
  CLASS CORE ;
  ORIGIN 0 0 ;
  FOREIGN gt2_6t_nand2_x4_w13_lvt 0 0 ;
  SIZE 0.3780 BY 0.1440 ;
  SYMMETRY X Y ;
  SITE gt2_6t ;
  PIN A
    DIRECTION INPUT ;
    USE SIGNAL ;
    PORT
      LAYER M0 ;
        RECT 0.0725 0.1160 0.3475 0.1280 ;
    END
  END A
  PIN B
    DIRECTION INPUT ;
    USE SIGNAL ;
    PORT
      LAYER M0 ;
        RECT 0.0305 0.0160 0.3055 0.0280 ;
    END
  END B
  PIN Y
    DIRECTION OUTPUT ;
    USE SIGNAL ;
    PORT
      LAYER M0 ;
        RECT 0.0095 0.0920 0.3685 0.1040 ;
    END
  END Y
  PIN VDD
    DIRECTION INOUT ;
    USE POWER ;
    SHAPE ABUTMENT ;
    PORT
      LAYER BPR ;
        RECT 0.0000 0.1280 0.3780 0.1600 ;
    END
  END VDD
  PIN VSS
    DIRECTION INOUT ;
    USE GROUND ;
    SHAPE ABUTMENT ;
    PORT
      LAYER BPR ;
        RECT 0.0000 -0.0160 0.3780 0.0160 ;
    END
  END VSS
END gt2_6t_nand2_x4_w13_lvt



MACRO gt2_6t_nand3_x1_w13_lvt
  CLASS CORE ;
  ORIGIN 0 0 ;
  FOREIGN gt2_6t_nand3_x1_w13_lvt 0 0 ;
  SIZE 0.1680 BY 0.1440 ;
  SYMMETRY X Y ;
  SITE gt2_6t ;
  PIN A
    DIRECTION INPUT ;
    USE SIGNAL ;
    PORT
      LAYER M0 ;
        RECT 0.1145 0.0400 0.1470 0.0520 ;
    END
  END A
  PIN B
    DIRECTION INPUT ;
    USE SIGNAL ;
    PORT
      LAYER M0 ;
        RECT 0.0725 0.1160 0.1050 0.1280 ;
    END
  END B
  PIN C
    DIRECTION INPUT ;
    USE SIGNAL ;
    PORT
      LAYER M0 ;
        RECT 0.0210 0.0160 0.0535 0.0280 ;
    END
  END C
  PIN Y
    DIRECTION OUTPUT ;
    USE SIGNAL ;
    PORT
      LAYER M0 ;
        RECT 0.0515 0.0920 0.1585 0.1040 ;
    END
  END Y
  PIN VDD
    DIRECTION INOUT ;
    USE POWER ;
    SHAPE ABUTMENT ;
    PORT
      LAYER BPR ;
        RECT 0.0000 0.1280 0.1680 0.1600 ;
    END
  END VDD
  PIN VSS
    DIRECTION INOUT ;
    USE GROUND ;
    SHAPE ABUTMENT ;
    PORT
      LAYER BPR ;
        RECT 0.0000 -0.0160 0.1680 0.0160 ;
    END
  END VSS
END gt2_6t_nand3_x1_w13_lvt

MACRO gt2_6t_nor2_x1_w13_lvt
  CLASS CORE ;
  ORIGIN 0 0 ;
  FOREIGN gt2_6t_nor2_x1_w13_lvt 0 0 ;
  SIZE 0.1260 BY 0.1440 ;
  SYMMETRY X Y ;
  SITE gt2_6t ;
  PIN A
    DIRECTION INPUT ;
    USE SIGNAL ;
    PORT
      LAYER M0 ;
        RECT 0.0210 0.0160 0.0535 0.0280 ;
    END
  END A
  PIN B
    DIRECTION INPUT ;
    USE SIGNAL ;
    PORT
      LAYER M0 ;
        RECT 0.0725 0.1160 0.1050 0.1280 ;
    END
  END B
  PIN Y
    DIRECTION OUTPUT ;
    USE SIGNAL ;
    PORT
      LAYER M0 ;
        RECT 0.0095 0.0400 0.1165 0.0520 ;
    END
  END Y
  PIN VDD
    DIRECTION INOUT ;
    USE POWER ;
    SHAPE ABUTMENT ;
    PORT
      LAYER BPR ;
        RECT 0.0000 0.1280 0.1260 0.1600 ;
    END
  END VDD
  PIN VSS
    DIRECTION INOUT ;
    USE GROUND ;
    SHAPE ABUTMENT ;
    PORT
      LAYER BPR ;
        RECT 0.0000 -0.0160 0.1260 0.0160 ;
    END
  END VSS
END gt2_6t_nor2_x1_w13_lvt

MACRO gt2_6t_nor2_x2_w13_lvt
  CLASS CORE ;
  ORIGIN 0 0 ;
  FOREIGN gt2_6t_nor2_x2_w13_lvt 0 0 ;
  SIZE 0.2100 BY 0.1440 ;
  SYMMETRY X Y ;
  SITE gt2_6t ;
  PIN A
    DIRECTION INPUT ;
    USE SIGNAL ;
    PORT
      LAYER M0 ;
        RECT 0.0305 0.0160 0.1375 0.0280 ;
    END
  END A
  PIN B
    DIRECTION INPUT ;
    USE SIGNAL ;
    PORT
      LAYER M0 ;
        RECT 0.0725 0.1160 0.1795 0.1280 ;
    END
  END B
  PIN Y
    DIRECTION OUTPUT ;
    USE SIGNAL ;
    PORT
      LAYER M0 ;
        RECT 0.0095 0.0400 0.2005 0.0520 ;
    END
  END Y
  PIN VDD
    DIRECTION INOUT ;
    USE POWER ;
    SHAPE ABUTMENT ;
    PORT
      LAYER BPR ;
        RECT 0.0000 0.1280 0.2100 0.1600 ;
    END
  END VDD
  PIN VSS
    DIRECTION INOUT ;
    USE GROUND ;
    SHAPE ABUTMENT ;
    PORT
      LAYER BPR ;
        RECT 0.0000 -0.0160 0.2100 0.0160 ;
    END
  END VSS
END gt2_6t_nor2_x2_w13_lvt

MACRO gt2_6t_nor2_x3_w13_lvt
  CLASS CORE ;
  ORIGIN 0 0 ;
  FOREIGN gt2_6t_nor2_x3_w13_lvt 0 0 ;
  SIZE 0.2940 BY 0.1440 ;
  SYMMETRY X Y ;
  SITE gt2_6t ;
  PIN A
    DIRECTION INPUT ;
    USE SIGNAL ;
    PORT
      LAYER M0 ;
        RECT 0.0725 0.1160 0.2635 0.1280 ;
    END
  END A
  PIN B
    DIRECTION INPUT ;
    USE SIGNAL ;
    PORT
      LAYER M0 ;
        RECT 0.0305 0.0160 0.2215 0.0280 ;
    END
  END B
  PIN Y
    DIRECTION OUTPUT ;
    USE SIGNAL ;
    PORT
      LAYER M0 ;
        RECT 0.0095 0.0400 0.2845 0.0520 ;
    END
  END Y
  PIN VDD
    DIRECTION INOUT ;
    USE POWER ;
    SHAPE ABUTMENT ;
    PORT
      LAYER BPR ;
        RECT 0.0000 0.1280 0.2940 0.1600 ;
    END
  END VDD
  PIN VSS
    DIRECTION INOUT ;
    USE GROUND ;
    SHAPE ABUTMENT ;
    PORT
      LAYER BPR ;
        RECT 0.0000 -0.0160 0.2940 0.0160 ;
    END
  END VSS
END gt2_6t_nor2_x3_w13_lvt

MACRO gt2_6t_nor2_x4_w13_lvt
  CLASS CORE ;
  ORIGIN 0 0 ;
  FOREIGN gt2_6t_nor2_x4_w13_lvt 0 0 ;
  SIZE 0.3780 BY 0.1440 ;
  SYMMETRY X Y ;
  SITE gt2_6t ;
  PIN A
    DIRECTION INPUT ;
    USE SIGNAL ;
    PORT
      LAYER M0 ;
        RECT 0.0305 0.0160 0.3055 0.0280 ;
    END
  END A
  PIN B
    DIRECTION INPUT ;
    USE SIGNAL ;
    PORT
      LAYER M0 ;
        RECT 0.0725 0.1160 0.3475 0.1280 ;
    END
  END B
  PIN Y
    DIRECTION OUTPUT ;
    USE SIGNAL ;
    PORT
      LAYER M0 ;
        RECT 0.0095 0.0400 0.3685 0.0520 ;
    END
  END Y
  PIN VDD
    DIRECTION INOUT ;
    USE POWER ;
    SHAPE ABUTMENT ;
    PORT
      LAYER BPR ;
        RECT 0.0000 0.1280 0.3780 0.1600 ;
    END
  END VDD
  PIN VSS
    DIRECTION INOUT ;
    USE GROUND ;
    SHAPE ABUTMENT ;
    PORT
      LAYER BPR ;
        RECT 0.0000 -0.0160 0.3780 0.0160 ;
    END
  END VSS
END gt2_6t_nor2_x4_w13_lvt


MACRO gt2_6t_nor3_x1_w13_lvt
  CLASS CORE ;
  ORIGIN 0 0 ;
  FOREIGN gt2_6t_nor3_x1_w13_lvt 0 0 ;
  SIZE 0.1680 BY 0.1440 ;
  SYMMETRY X Y ;
  SITE gt2_6t ;
  PIN A
    DIRECTION INPUT ;
    USE SIGNAL ;
    PORT
      LAYER M0 ;
        RECT 0.0725 0.0160 0.1050 0.0280 ;
    END
  END A
  PIN B
    DIRECTION INPUT ;
    USE SIGNAL ;
    PORT
      LAYER M0 ;
        RECT 0.0210 0.0920 0.0535 0.1040 ;
    END
  END B
  PIN C
    DIRECTION INPUT ;
    USE SIGNAL ;
    PORT
      LAYER M0 ;
        RECT 0.1145 0.1160 0.1470 0.1280 ;
    END
  END C
  PIN Y
    DIRECTION OUTPUT ;
    USE SIGNAL ;
    PORT
      LAYER M0 ;
        RECT 0.0515 0.0400 0.1585 0.0520 ;
    END
  END Y
  PIN VDD
    DIRECTION INOUT ;
    USE POWER ;
    SHAPE ABUTMENT ;
    PORT
      LAYER BPR ;
        RECT 0.0000 0.1280 0.1680 0.1600 ;
    END
  END VDD
  PIN VSS
    DIRECTION INOUT ;
    USE GROUND ;
    SHAPE ABUTMENT ;
    PORT
      LAYER BPR ;
        RECT 0.0000 -0.0160 0.1680 0.0160 ;
    END
  END VSS
END gt2_6t_nor3_x1_w13_lvt

MACRO gt2_6t_oa211_x1_w13_lvt
  CLASS CORE ;
  ORIGIN 0 0 ;
  FOREIGN gt2_6t_oa211_x1_w13_lvt 0 0 ;
  SIZE 0.2520 BY 0.1440 ;
  SYMMETRY X Y ;
  SITE gt2_6t ;
  PIN A1
    DIRECTION INPUT ;
    USE SIGNAL ;
    PORT
      LAYER M0 ;
        RECT 0.1985 0.1160 0.2310 0.1280 ;
    END
  END A1
  PIN A2
    DIRECTION INPUT ;
    USE SIGNAL ;
    PORT
      LAYER M0 ;
        RECT 0.1470 0.1160 0.1795 0.1280 ;
    END
  END A2
  PIN B
    DIRECTION INPUT ;
    USE SIGNAL ;
    PORT
      LAYER M0 ;
        RECT 0.0725 0.1160 0.1050 0.1280 ;
    END
  END B
  PIN C
    DIRECTION INPUT ;
    USE SIGNAL ;
    PORT
      LAYER M0 ;
        RECT 0.1145 0.0160 0.1470 0.0280 ;
    END
  END C
  PIN Y
    DIRECTION OUTPUT ;
    USE SIGNAL ;
    PORT
      LAYER M0 ;
        RECT 0.0095 0.0400 0.0420 0.0520 ;
    END
  END Y
  PIN VDD
    DIRECTION INOUT ;
    USE POWER ;
    SHAPE ABUTMENT ;
    PORT
      LAYER BPR ;
        RECT 0.0000 0.1280 0.2520 0.1600 ;
    END
  END VDD
  PIN VSS
    DIRECTION INOUT ;
    USE GROUND ;
    SHAPE ABUTMENT ;
    PORT
      LAYER BPR ;
        RECT 0.0000 -0.0160 0.2520 0.0160 ;
    END
  END VSS
  OBS
    LAYER M1 ;
      RECT 0.1960 0.0110 0.2100 0.1090 ;
    LAYER M0 ;
      RECT 0.1355 0.0400 0.2425 0.0520 ;
      RECT 0.1775 0.0160 0.2180 0.0280 ;
      RECT 0.0305 0.0920 0.2425 0.1040 ;
    LAYER V0 ;
      RECT 0.1960 0.0160 0.2100 0.0280 ;
      RECT 0.1960 0.0920 0.2100 0.1040 ;
  END
END gt2_6t_oa211_x1_w13_lvt

MACRO gt2_6t_oa21_x1_w13_lvt
  CLASS CORE ;
  ORIGIN 0 0 ;
  FOREIGN gt2_6t_oa21_x1_w13_lvt 0 0 ;
  SIZE 0.2100 BY 0.1440 ;
  SYMMETRY X Y ;
  SITE gt2_6t ;
  PIN A1
    DIRECTION INPUT ;
    USE SIGNAL ;
    PORT
      LAYER M0 ;
        RECT 0.0630 0.1160 0.0955 0.1280 ;
    END
  END A1
  PIN A2
    DIRECTION INPUT ;
    USE SIGNAL ;
    PORT
      LAYER M0 ;
        RECT 0.0305 0.0920 0.0630 0.1040 ;
    END
  END A2
  PIN B
    DIRECTION INPUT ;
    USE SIGNAL ;
    PORT
      LAYER M0 ;
        RECT 0.1145 0.1160 0.1470 0.1280 ;
    END
  END B
  PIN Y
    DIRECTION OUTPUT ;
    USE SIGNAL ;
    PORT
      LAYER M0 ;
        RECT 0.1680 0.0400 0.2005 0.0520 ;
    END
  END Y
  PIN VDD
    DIRECTION INOUT ;
    USE POWER ;
    SHAPE ABUTMENT ;
    PORT
      LAYER BPR ;
        RECT 0.0000 0.1280 0.2100 0.1600 ;
    END
  END VDD
  PIN VSS
    DIRECTION INOUT ;
    USE GROUND ;
    SHAPE ABUTMENT ;
    PORT
      LAYER BPR ;
        RECT 0.0000 -0.0160 0.2100 0.0160 ;
    END
  END VSS
  OBS
    LAYER M0 ;
      RECT 0.0095 0.0400 0.1165 0.0520 ;
      RECT 0.0515 0.0160 0.1795 0.0280 ;
      RECT 0.0935 0.0920 0.1795 0.1040 ;
  END
END gt2_6t_oa21_x1_w13_lvt

MACRO gt2_6t_oa21_x3_w13_lvt
  CLASS CORE ;
  ORIGIN 0 0 ;
  FOREIGN gt2_6t_oa21_x3_w13_lvt 0 0 ;
  SIZE 0.4620 BY 0.1440 ;
  SYMMETRY X Y ;
  SITE gt2_6t ;
  PIN A1
    DIRECTION INPUT ;
    USE SIGNAL ;
    PORT
      LAYER M0 ;
        RECT 0.3665 0.1160 0.4315 0.1280 ;
    END
  END A1
  PIN A2
    DIRECTION INPUT ;
    USE SIGNAL ;
    PORT
      LAYER M0 ;
        RECT 0.1985 0.1160 0.3475 0.1280 ;
    END
  END A2
  PIN B
    DIRECTION INPUT ;
    USE SIGNAL ;
    PORT
      LAYER M0 ;
        RECT 0.2405 0.0450 0.3055 0.0570 ;
    END
  END B
  PIN Y
    DIRECTION OUTPUT ;
    USE SIGNAL ;
    PORT
      LAYER M1 ;
        RECT 0.0560 0.0110 0.0700 0.1330 ;
      LAYER M0 ;
        RECT 0.0480 0.0160 0.1585 0.0280 ;
        RECT 0.0095 0.1160 0.1165 0.1280 ;
      LAYER V0 ;
        RECT 0.0560 0.0160 0.0700 0.0280 ;
        RECT 0.0560 0.1160 0.0700 0.1280 ;
    END
  END Y
  PIN VDD
    DIRECTION INOUT ;
    USE POWER ;
    SHAPE ABUTMENT ;
    PORT
      LAYER BPR ;
        RECT 0.0000 0.1280 0.4620 0.1600 ;
    END
  END VDD
  PIN VSS
    DIRECTION INOUT ;
    USE GROUND ;
    SHAPE ABUTMENT ;
    PORT
      LAYER BPR ;
        RECT 0.0000 -0.0160 0.4620 0.0160 ;
    END
  END VSS
  OBS
    LAYER M2 ;
      RECT 0.1890 0.0880 0.4110 0.1020 ;
      RECT 0.1630 0.0400 0.3830 0.0540 ;
    LAYER M1 ;
      RECT 0.1960 0.0400 0.2100 0.1070 ;
      RECT 0.3920 0.0400 0.4060 0.1070 ;
      RECT 0.2240 0.0480 0.2380 0.1200 ;
      RECT 0.1680 0.0350 0.1820 0.1040 ;
      RECT 0.3640 0.0350 0.3780 0.1040 ;
    LAYER M0 ;
      RECT 0.2195 0.0160 0.4105 0.0280 ;
      RECT 0.0305 0.0450 0.2180 0.0570 ;
      RECT 0.3455 0.0450 0.4525 0.0570 ;
      RECT 0.2175 0.0870 0.3265 0.0990 ;
      RECT 0.1600 0.0870 0.2005 0.0990 ;
      RECT 0.3455 0.0870 0.4525 0.0990 ;
    LAYER V1 ;
      RECT 0.1960 0.0880 0.2100 0.1020 ;
      RECT 0.2240 0.0880 0.2380 0.1020 ;
      RECT 0.3920 0.0880 0.4060 0.1020 ;
      RECT 0.1680 0.0400 0.1820 0.0540 ;
      RECT 0.3640 0.0400 0.3780 0.0540 ;
    LAYER V0 ;
      RECT 0.1960 0.0450 0.2100 0.0570 ;
      RECT 0.3920 0.0450 0.4060 0.0570 ;
      RECT 0.2240 0.0870 0.2380 0.0990 ;
      RECT 0.1680 0.0870 0.1820 0.0990 ;
      RECT 0.3640 0.0870 0.3780 0.0990 ;
  END
END gt2_6t_oa21_x3_w13_lvt

MACRO gt2_6t_oa22_x1_w13_lvt
  CLASS CORE ;
  ORIGIN 0 0 ;
  FOREIGN gt2_6t_oa22_x1_w13_lvt 0 0 ;
  SIZE 0.2940 BY 0.1440 ;
  SYMMETRY X Y ;
  SITE gt2_6t ;
  PIN A1
    DIRECTION INPUT ;
    USE SIGNAL ;
    PORT
      LAYER M0 ;
        RECT 0.0725 0.1160 0.1050 0.1280 ;
    END
  END A1
  PIN A2
    DIRECTION INPUT ;
    USE SIGNAL ;
    PORT
      LAYER M0 ;
        RECT 0.0210 0.0920 0.0535 0.1040 ;
    END
  END A2
  PIN B1
    DIRECTION INPUT ;
    USE SIGNAL ;
    PORT
      LAYER M0 ;
        RECT 0.1985 0.1160 0.2310 0.1280 ;
    END
  END B1
  PIN B2
    DIRECTION INPUT ;
    USE SIGNAL ;
    PORT
      LAYER M0 ;
        RECT 0.1470 0.0160 0.1795 0.0280 ;
    END
  END B2
  PIN Y
    DIRECTION OUTPUT ;
    USE SIGNAL ;
    PORT
      LAYER M0 ;
        RECT 0.2520 0.0400 0.2845 0.0520 ;
    END
  END Y
  PIN VDD
    DIRECTION INOUT ;
    USE POWER ;
    SHAPE ABUTMENT ;
    PORT
      LAYER BPR ;
        RECT 0.0000 0.1280 0.2940 0.1600 ;
    END
  END VDD
  PIN VSS
    DIRECTION INOUT ;
    USE GROUND ;
    SHAPE ABUTMENT ;
    PORT
      LAYER BPR ;
        RECT 0.0000 -0.0160 0.2940 0.0160 ;
    END
  END VSS
  OBS
    LAYER M0 ;
      RECT 0.0515 0.0400 0.2005 0.0520 ;
      RECT 0.0095 0.0160 0.1165 0.0280 ;
      RECT 0.0935 0.0920 0.2635 0.1040 ;
  END
END gt2_6t_oa22_x1_w13_lvt

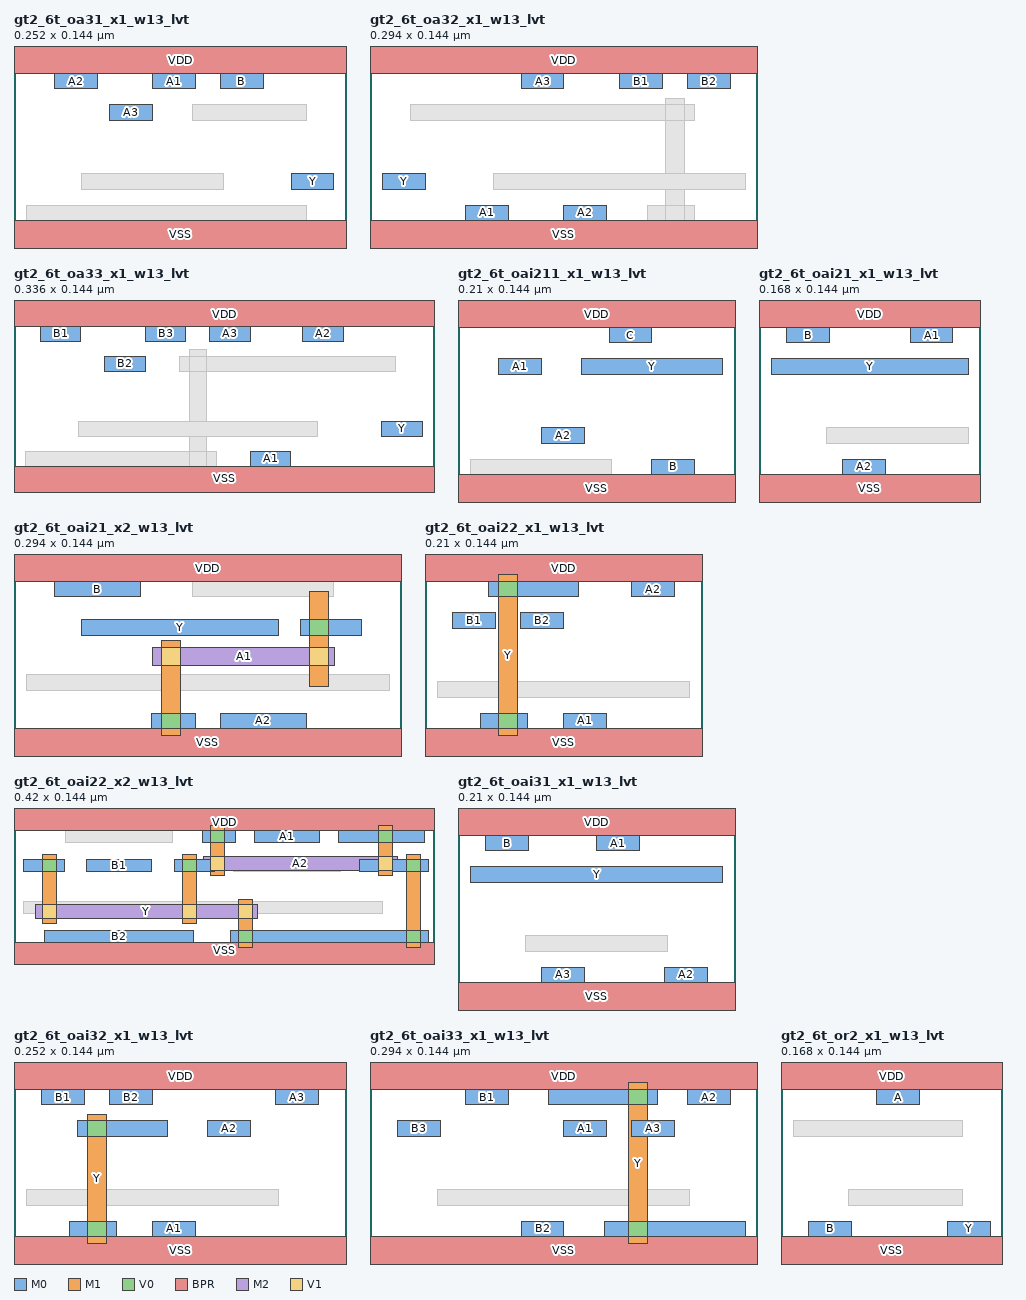
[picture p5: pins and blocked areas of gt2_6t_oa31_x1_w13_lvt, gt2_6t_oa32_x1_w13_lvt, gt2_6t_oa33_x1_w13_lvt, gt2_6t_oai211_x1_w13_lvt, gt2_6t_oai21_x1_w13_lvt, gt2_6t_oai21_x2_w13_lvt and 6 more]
MACRO gt2_6t_oa31_x1_w13_lvt
  CLASS CORE ;
  ORIGIN 0 0 ;
  FOREIGN gt2_6t_oa31_x1_w13_lvt 0 0 ;
  SIZE 0.2520 BY 0.1440 ;
  SYMMETRY X Y ;
  SITE gt2_6t ;
  PIN A1
    DIRECTION INPUT ;
    USE SIGNAL ;
    PORT
      LAYER M0 ;
        RECT 0.1050 0.1160 0.1375 0.1280 ;
    END
  END A1
  PIN A2
    DIRECTION INPUT ;
    USE SIGNAL ;
    PORT
      LAYER M0 ;
        RECT 0.0305 0.1160 0.0630 0.1280 ;
    END
  END A2
  PIN A3
    DIRECTION INPUT ;
    USE SIGNAL ;
    PORT
      LAYER M0 ;
        RECT 0.0725 0.0920 0.1050 0.1040 ;
    END
  END A3
  PIN B
    DIRECTION INPUT ;
    USE SIGNAL ;
    PORT
      LAYER M0 ;
        RECT 0.1565 0.1160 0.1890 0.1280 ;
    END
  END B
  PIN Y
    DIRECTION OUTPUT ;
    USE SIGNAL ;
    PORT
      LAYER M0 ;
        RECT 0.2100 0.0400 0.2425 0.0520 ;
    END
  END Y
  PIN VDD
    DIRECTION INOUT ;
    USE POWER ;
    SHAPE ABUTMENT ;
    PORT
      LAYER BPR ;
        RECT 0.0000 0.1280 0.2520 0.1600 ;
    END
  END VDD
  PIN VSS
    DIRECTION INOUT ;
    USE GROUND ;
    SHAPE ABUTMENT ;
    PORT
      LAYER BPR ;
        RECT 0.0000 -0.0160 0.2520 0.0160 ;
    END
  END VSS
  OBS
    LAYER M0 ;
      RECT 0.0095 0.0160 0.2215 0.0280 ;
      RECT 0.1355 0.0920 0.2215 0.1040 ;
      RECT 0.0515 0.0400 0.1585 0.0520 ;
  END
END gt2_6t_oa31_x1_w13_lvt

MACRO gt2_6t_oa32_x1_w13_lvt
  CLASS CORE ;
  ORIGIN 0 0 ;
  FOREIGN gt2_6t_oa32_x1_w13_lvt 0 0 ;
  SIZE 0.2940 BY 0.1440 ;
  SYMMETRY X Y ;
  SITE gt2_6t ;
  PIN A1
    DIRECTION INPUT ;
    USE SIGNAL ;
    PORT
      LAYER M0 ;
        RECT 0.0725 0.0160 0.1050 0.0280 ;
    END
  END A1
  PIN A2
    DIRECTION INPUT ;
    USE SIGNAL ;
    PORT
      LAYER M0 ;
        RECT 0.1470 0.0160 0.1795 0.0280 ;
    END
  END A2
  PIN A3
    DIRECTION INPUT ;
    USE SIGNAL ;
    PORT
      LAYER M0 ;
        RECT 0.1145 0.1160 0.1470 0.1280 ;
    END
  END A3
  PIN B1
    DIRECTION INPUT ;
    USE SIGNAL ;
    PORT
      LAYER M0 ;
        RECT 0.1890 0.1160 0.2215 0.1280 ;
    END
  END B1
  PIN B2
    DIRECTION INPUT ;
    USE SIGNAL ;
    PORT
      LAYER M0 ;
        RECT 0.2405 0.1160 0.2730 0.1280 ;
    END
  END B2
  PIN Y
    DIRECTION OUTPUT ;
    USE SIGNAL ;
    PORT
      LAYER M0 ;
        RECT 0.0095 0.0400 0.0420 0.0520 ;
    END
  END Y
  PIN VDD
    DIRECTION INOUT ;
    USE POWER ;
    SHAPE ABUTMENT ;
    PORT
      LAYER BPR ;
        RECT 0.0000 0.1280 0.2940 0.1600 ;
    END
  END VDD
  PIN VSS
    DIRECTION INOUT ;
    USE GROUND ;
    SHAPE ABUTMENT ;
    PORT
      LAYER BPR ;
        RECT 0.0000 -0.0160 0.2940 0.0160 ;
    END
  END VSS
  OBS
    LAYER M1 ;
      RECT 0.2240 0.0110 0.2380 0.1090 ;
    LAYER M0 ;
      RECT 0.0935 0.0400 0.2845 0.0520 ;
      RECT 0.2100 0.0160 0.2460 0.0280 ;
      RECT 0.0305 0.0920 0.2460 0.1040 ;
    LAYER V0 ;
      RECT 0.2240 0.0160 0.2380 0.0280 ;
      RECT 0.2240 0.0920 0.2380 0.1040 ;
  END
END gt2_6t_oa32_x1_w13_lvt

MACRO gt2_6t_oa33_x1_w13_lvt
  CLASS CORE ;
  ORIGIN 0 0 ;
  FOREIGN gt2_6t_oa33_x1_w13_lvt 0 0 ;
  SIZE 0.3360 BY 0.1440 ;
  SYMMETRY X Y ;
  SITE gt2_6t ;
  PIN A1
    DIRECTION INPUT ;
    USE SIGNAL ;
    PORT
      LAYER M0 ;
        RECT 0.1890 0.0160 0.2215 0.0280 ;
    END
  END A1
  PIN A2
    DIRECTION INPUT ;
    USE SIGNAL ;
    PORT
      LAYER M0 ;
        RECT 0.2310 0.1160 0.2635 0.1280 ;
    END
  END A2
  PIN A3
    DIRECTION INPUT ;
    USE SIGNAL ;
    PORT
      LAYER M0 ;
        RECT 0.1565 0.1160 0.1890 0.1280 ;
    END
  END A3
  PIN B1
    DIRECTION INPUT ;
    USE SIGNAL ;
    PORT
      LAYER M0 ;
        RECT 0.0210 0.1160 0.0535 0.1280 ;
    END
  END B1
  PIN B2
    DIRECTION INPUT ;
    USE SIGNAL ;
    PORT
      LAYER M0 ;
        RECT 0.0725 0.0920 0.1050 0.1040 ;
    END
  END B2
  PIN B3
    DIRECTION INPUT ;
    USE SIGNAL ;
    PORT
      LAYER M0 ;
        RECT 0.1050 0.1160 0.1375 0.1280 ;
    END
  END B3
  PIN Y
    DIRECTION OUTPUT ;
    USE SIGNAL ;
    PORT
      LAYER M0 ;
        RECT 0.2940 0.0400 0.3265 0.0520 ;
    END
  END Y
  PIN VDD
    DIRECTION INOUT ;
    USE POWER ;
    SHAPE ABUTMENT ;
    PORT
      LAYER BPR ;
        RECT 0.0000 0.1280 0.3360 0.1600 ;
    END
  END VDD
  PIN VSS
    DIRECTION INOUT ;
    USE GROUND ;
    SHAPE ABUTMENT ;
    PORT
      LAYER BPR ;
        RECT 0.0000 -0.0160 0.3360 0.0160 ;
    END
  END VSS
  OBS
    LAYER M1 ;
      RECT 0.1400 0.0110 0.1540 0.1090 ;
    LAYER M0 ;
      RECT 0.0095 0.0160 0.1620 0.0280 ;
      RECT 0.1320 0.0920 0.3055 0.1040 ;
      RECT 0.0515 0.0400 0.2425 0.0520 ;
    LAYER V0 ;
      RECT 0.1400 0.0160 0.1540 0.0280 ;
      RECT 0.1400 0.0920 0.1540 0.1040 ;
  END
END gt2_6t_oa33_x1_w13_lvt

MACRO gt2_6t_oai211_x1_w13_lvt
  CLASS CORE ;
  ORIGIN 0 0 ;
  FOREIGN gt2_6t_oai211_x1_w13_lvt 0 0 ;
  SIZE 0.2100 BY 0.1440 ;
  SYMMETRY X Y ;
  SITE gt2_6t ;
  PIN A1
    DIRECTION INPUT ;
    USE SIGNAL ;
    PORT
      LAYER M0 ;
        RECT 0.0305 0.0920 0.0630 0.1040 ;
    END
  END A1
  PIN A2
    DIRECTION INPUT ;
    USE SIGNAL ;
    PORT
      LAYER M0 ;
        RECT 0.0630 0.0400 0.0955 0.0520 ;
    END
  END A2
  PIN B
    DIRECTION INPUT ;
    USE SIGNAL ;
    PORT
      LAYER M0 ;
        RECT 0.1470 0.0160 0.1795 0.0280 ;
    END
  END B
  PIN C
    DIRECTION INPUT ;
    USE SIGNAL ;
    PORT
      LAYER M0 ;
        RECT 0.1145 0.1160 0.1470 0.1280 ;
    END
  END C
  PIN Y
    DIRECTION OUTPUT ;
    USE SIGNAL ;
    PORT
      LAYER M0 ;
        RECT 0.0935 0.0920 0.2005 0.1040 ;
    END
  END Y
  PIN VDD
    DIRECTION INOUT ;
    USE POWER ;
    SHAPE ABUTMENT ;
    PORT
      LAYER BPR ;
        RECT 0.0000 0.1280 0.2100 0.1600 ;
    END
  END VDD
  PIN VSS
    DIRECTION INOUT ;
    USE GROUND ;
    SHAPE ABUTMENT ;
    PORT
      LAYER BPR ;
        RECT 0.0000 -0.0160 0.2100 0.0160 ;
    END
  END VSS
  OBS
    LAYER M0 ;
      RECT 0.0095 0.0160 0.1165 0.0280 ;
  END
END gt2_6t_oai211_x1_w13_lvt

MACRO gt2_6t_oai21_x1_w13_lvt
  CLASS CORE ;
  ORIGIN 0 0 ;
  FOREIGN gt2_6t_oai21_x1_w13_lvt 0 0 ;
  SIZE 0.1680 BY 0.1440 ;
  SYMMETRY X Y ;
  SITE gt2_6t ;
  PIN A1
    DIRECTION INPUT ;
    USE SIGNAL ;
    PORT
      LAYER M0 ;
        RECT 0.1145 0.1160 0.1470 0.1280 ;
    END
  END A1
  PIN A2
    DIRECTION INPUT ;
    USE SIGNAL ;
    PORT
      LAYER M0 ;
        RECT 0.0630 0.0160 0.0955 0.0280 ;
    END
  END A2
  PIN B
    DIRECTION INPUT ;
    USE SIGNAL ;
    PORT
      LAYER M0 ;
        RECT 0.0210 0.1160 0.0535 0.1280 ;
    END
  END B
  PIN Y
    DIRECTION OUTPUT ;
    USE SIGNAL ;
    PORT
      LAYER M0 ;
        RECT 0.0095 0.0920 0.1585 0.1040 ;
    END
  END Y
  PIN VDD
    DIRECTION INOUT ;
    USE POWER ;
    SHAPE ABUTMENT ;
    PORT
      LAYER BPR ;
        RECT 0.0000 0.1280 0.1680 0.1600 ;
    END
  END VDD
  PIN VSS
    DIRECTION INOUT ;
    USE GROUND ;
    SHAPE ABUTMENT ;
    PORT
      LAYER BPR ;
        RECT 0.0000 -0.0160 0.1680 0.0160 ;
    END
  END VSS
  OBS
    LAYER M0 ;
      RECT 0.0515 0.0400 0.1585 0.0520 ;
  END
END gt2_6t_oai21_x1_w13_lvt


MACRO gt2_6t_oai21_x2_w13_lvt
  CLASS CORE ;
  ORIGIN 0 0 ;
  FOREIGN gt2_6t_oai21_x2_w13_lvt 0 0 ;
  SIZE 0.2940 BY 0.1440 ;
  SYMMETRY X Y ;
  SITE gt2_6t ;
  PIN A1
    DIRECTION INPUT ;
    USE SIGNAL ;
    PORT
      LAYER M2 ;
        RECT 0.1050 0.0640 0.2430 0.0780 ;
      LAYER M1 ;
        RECT 0.1120 0.0110 0.1260 0.0830 ;
        RECT 0.2240 0.0480 0.2380 0.1200 ;
      LAYER M0 ;
        RECT 0.1040 0.0160 0.1375 0.0280 ;
        RECT 0.2175 0.0870 0.2635 0.0990 ;
      LAYER V1 ;
        RECT 0.1120 0.0640 0.1260 0.0780 ;
        RECT 0.2240 0.0640 0.2380 0.0780 ;
      LAYER V0 ;
        RECT 0.1120 0.0160 0.1260 0.0280 ;
        RECT 0.2240 0.0870 0.2380 0.0990 ;
    END
  END A1
  PIN A2
    DIRECTION INPUT ;
    USE SIGNAL ;
    PORT
      LAYER M0 ;
        RECT 0.1565 0.0160 0.2215 0.0280 ;
    END
  END A2
  PIN B
    DIRECTION INPUT ;
    USE SIGNAL ;
    PORT
      LAYER M0 ;
        RECT 0.0305 0.1160 0.0955 0.1280 ;
    END
  END B
  PIN Y
    DIRECTION OUTPUT ;
    USE SIGNAL ;
    PORT
      LAYER M0 ;
        RECT 0.0515 0.0870 0.2005 0.0990 ;
    END
  END Y
  PIN VDD
    DIRECTION INOUT ;
    USE POWER ;
    SHAPE ABUTMENT ;
    PORT
      LAYER BPR ;
        RECT 0.0000 0.1280 0.2940 0.1600 ;
    END
  END VDD
  PIN VSS
    DIRECTION INOUT ;
    USE GROUND ;
    SHAPE ABUTMENT ;
    PORT
      LAYER BPR ;
        RECT 0.0000 -0.0160 0.2940 0.0160 ;
    END
  END VSS
  OBS
    LAYER M0 ;
      RECT 0.0095 0.0450 0.2845 0.0570 ;
      RECT 0.1355 0.1160 0.2425 0.1280 ;
  END
END gt2_6t_oai21_x2_w13_lvt

MACRO gt2_6t_oai22_x1_w13_lvt
  CLASS CORE ;
  ORIGIN 0 0 ;
  FOREIGN gt2_6t_oai22_x1_w13_lvt 0 0 ;
  SIZE 0.2100 BY 0.1440 ;
  SYMMETRY X Y ;
  SITE gt2_6t ;
  PIN A1
    DIRECTION INPUT ;
    USE SIGNAL ;
    PORT
      LAYER M0 ;
        RECT 0.1050 0.0160 0.1375 0.0280 ;
    END
  END A1
  PIN A2
    DIRECTION INPUT ;
    USE SIGNAL ;
    PORT
      LAYER M0 ;
        RECT 0.1565 0.1160 0.1890 0.1280 ;
    END
  END A2
  PIN B1
    DIRECTION INPUT ;
    USE SIGNAL ;
    PORT
      LAYER M0 ;
        RECT 0.0210 0.0920 0.0535 0.1040 ;
    END
  END B1
  PIN B2
    DIRECTION INPUT ;
    USE SIGNAL ;
    PORT
      LAYER M0 ;
        RECT 0.0725 0.0920 0.1050 0.1040 ;
    END
  END B2
  PIN Y
    DIRECTION OUTPUT ;
    USE SIGNAL ;
    PORT
      LAYER M1 ;
        RECT 0.0560 0.0110 0.0700 0.1330 ;
      LAYER M0 ;
        RECT 0.0420 0.0160 0.0780 0.0280 ;
        RECT 0.0480 0.1160 0.1165 0.1280 ;
      LAYER V0 ;
        RECT 0.0560 0.0160 0.0700 0.0280 ;
        RECT 0.0560 0.1160 0.0700 0.1280 ;
    END
  END Y
  PIN VDD
    DIRECTION INOUT ;
    USE POWER ;
    SHAPE ABUTMENT ;
    PORT
      LAYER BPR ;
        RECT 0.0000 0.1280 0.2100 0.1600 ;
    END
  END VDD
  PIN VSS
    DIRECTION INOUT ;
    USE GROUND ;
    SHAPE ABUTMENT ;
    PORT
      LAYER BPR ;
        RECT 0.0000 -0.0160 0.2100 0.0160 ;
    END
  END VSS
  OBS
    LAYER M0 ;
      RECT 0.0095 0.0400 0.2005 0.0520 ;
  END
END gt2_6t_oai22_x1_w13_lvt


MACRO gt2_6t_oai22_x2_w13_lvt
  CLASS CORE ;
  ORIGIN 0 0 ;
  FOREIGN gt2_6t_oai22_x2_w13_lvt 0 0 ;
  SIZE 0.4200 BY 0.1440 ;
  SYMMETRY X Y ;
  SITE gt2_6t ;
  PIN A1
    DIRECTION INPUT ;
    USE SIGNAL ;
    PORT
      LAYER M0 ;
        RECT 0.2405 0.1160 0.3055 0.1280 ;
    END
  END A1
  PIN A2
    DIRECTION INPUT ;
    USE SIGNAL ;
    PORT
      LAYER M2 ;
        RECT 0.1890 0.0880 0.3830 0.1020 ;
      LAYER M1 ;
        RECT 0.1960 0.0830 0.2100 0.1330 ;
        RECT 0.3640 0.0830 0.3780 0.1330 ;
      LAYER M0 ;
        RECT 0.1880 0.1160 0.2215 0.1280 ;
        RECT 0.3245 0.1160 0.4105 0.1280 ;
      LAYER V1 ;
        RECT 0.1960 0.0880 0.2100 0.1020 ;
        RECT 0.3640 0.0880 0.3780 0.1020 ;
      LAYER V0 ;
        RECT 0.1960 0.1160 0.2100 0.1280 ;
        RECT 0.3640 0.1160 0.3780 0.1280 ;
    END
  END A2
  PIN B1
    DIRECTION INPUT ;
    USE SIGNAL ;
    PORT
      LAYER M0 ;
        RECT 0.0725 0.0870 0.1375 0.0990 ;
    END
  END B1
  PIN B2
    DIRECTION INPUT ;
    USE SIGNAL ;
    PORT
      LAYER M0 ;
        RECT 0.0305 0.0160 0.1795 0.0280 ;
    END
  END B2
  PIN Y
    DIRECTION OUTPUT ;
    USE SIGNAL ;
    PORT
      LAYER M2 ;
        RECT 0.0210 0.0400 0.2430 0.0540 ;
      LAYER M1 ;
        RECT 0.2240 0.0110 0.2380 0.0590 ;
        RECT 0.0280 0.0350 0.0420 0.1040 ;
        RECT 0.1680 0.0350 0.1820 0.1040 ;
        RECT 0.3920 0.0110 0.4060 0.1040 ;
      LAYER M0 ;
        RECT 0.2160 0.0160 0.4140 0.0280 ;
        RECT 0.0095 0.0870 0.0500 0.0990 ;
        RECT 0.1600 0.0870 0.2005 0.0990 ;
        RECT 0.3455 0.0870 0.4140 0.0990 ;
      LAYER V1 ;
        RECT 0.0280 0.0400 0.0420 0.0540 ;
        RECT 0.1680 0.0400 0.1820 0.0540 ;
        RECT 0.2240 0.0400 0.2380 0.0540 ;
      LAYER V0 ;
        RECT 0.2240 0.0160 0.2380 0.0280 ;
        RECT 0.3920 0.0160 0.4060 0.0280 ;
        RECT 0.0280 0.0870 0.0420 0.0990 ;
        RECT 0.1680 0.0870 0.1820 0.0990 ;
        RECT 0.3920 0.0870 0.4060 0.0990 ;
    END
  END Y
  PIN VDD
    DIRECTION INOUT ;
    USE POWER ;
    SHAPE ABUTMENT ;
    PORT
      LAYER BPR ;
        RECT 0.0000 0.1280 0.4200 0.1600 ;
    END
  END VDD
  PIN VSS
    DIRECTION INOUT ;
    USE GROUND ;
    SHAPE ABUTMENT ;
    PORT
      LAYER BPR ;
        RECT 0.0000 -0.0160 0.4200 0.0160 ;
    END
  END VSS
  OBS
    LAYER M0 ;
      RECT 0.0095 0.0450 0.3685 0.0570 ;
      RECT 0.0515 0.1160 0.1585 0.1280 ;
      RECT 0.2195 0.0870 0.3265 0.0990 ;
  END
END gt2_6t_oai22_x2_w13_lvt

MACRO gt2_6t_oai31_x1_w13_lvt
  CLASS CORE ;
  ORIGIN 0 0 ;
  FOREIGN gt2_6t_oai31_x1_w13_lvt 0 0 ;
  SIZE 0.2100 BY 0.1440 ;
  SYMMETRY X Y ;
  SITE gt2_6t ;
  PIN A1
    DIRECTION INPUT ;
    USE SIGNAL ;
    PORT
      LAYER M0 ;
        RECT 0.1050 0.1160 0.1375 0.1280 ;
    END
  END A1
  PIN A2
    DIRECTION INPUT ;
    USE SIGNAL ;
    PORT
      LAYER M0 ;
        RECT 0.1565 0.0160 0.1890 0.0280 ;
    END
  END A2
  PIN A3
    DIRECTION INPUT ;
    USE SIGNAL ;
    PORT
      LAYER M0 ;
        RECT 0.0630 0.0160 0.0955 0.0280 ;
    END
  END A3
  PIN B
    DIRECTION INPUT ;
    USE SIGNAL ;
    PORT
      LAYER M0 ;
        RECT 0.0210 0.1160 0.0535 0.1280 ;
    END
  END B
  PIN Y
    DIRECTION OUTPUT ;
    USE SIGNAL ;
    PORT
      LAYER M0 ;
        RECT 0.0095 0.0920 0.2005 0.1040 ;
    END
  END Y
  PIN VDD
    DIRECTION INOUT ;
    USE POWER ;
    SHAPE ABUTMENT ;
    PORT
      LAYER BPR ;
        RECT 0.0000 0.1280 0.2100 0.1600 ;
    END
  END VDD
  PIN VSS
    DIRECTION INOUT ;
    USE GROUND ;
    SHAPE ABUTMENT ;
    PORT
      LAYER BPR ;
        RECT 0.0000 -0.0160 0.2100 0.0160 ;
    END
  END VSS
  OBS
    LAYER M0 ;
      RECT 0.0515 0.0400 0.1585 0.0520 ;
  END
END gt2_6t_oai31_x1_w13_lvt


MACRO gt2_6t_oai32_x1_w13_lvt
  CLASS CORE ;
  ORIGIN 0 0 ;
  FOREIGN gt2_6t_oai32_x1_w13_lvt 0 0 ;
  SIZE 0.2520 BY 0.1440 ;
  SYMMETRY X Y ;
  SITE gt2_6t ;
  PIN A1
    DIRECTION INPUT ;
    USE SIGNAL ;
    PORT
      LAYER M0 ;
        RECT 0.1050 0.0160 0.1375 0.0280 ;
    END
  END A1
  PIN A2
    DIRECTION INPUT ;
    USE SIGNAL ;
    PORT
      LAYER M0 ;
        RECT 0.1470 0.0920 0.1795 0.1040 ;
    END
  END A2
  PIN A3
    DIRECTION INPUT ;
    USE SIGNAL ;
    PORT
      LAYER M0 ;
        RECT 0.1985 0.1160 0.2310 0.1280 ;
    END
  END A3
  PIN B1
    DIRECTION INPUT ;
    USE SIGNAL ;
    PORT
      LAYER M0 ;
        RECT 0.0210 0.1160 0.0535 0.1280 ;
    END
  END B1
  PIN B2
    DIRECTION INPUT ;
    USE SIGNAL ;
    PORT
      LAYER M0 ;
        RECT 0.0725 0.1160 0.1050 0.1280 ;
    END
  END B2
  PIN Y
    DIRECTION OUTPUT ;
    USE SIGNAL ;
    PORT
      LAYER M1 ;
        RECT 0.0560 0.0110 0.0700 0.1090 ;
      LAYER M0 ;
        RECT 0.0420 0.0160 0.0780 0.0280 ;
        RECT 0.0480 0.0920 0.1165 0.1040 ;
      LAYER V0 ;
        RECT 0.0560 0.0160 0.0700 0.0280 ;
        RECT 0.0560 0.0920 0.0700 0.1040 ;
    END
  END Y
  PIN VDD
    DIRECTION INOUT ;
    USE POWER ;
    SHAPE ABUTMENT ;
    PORT
      LAYER BPR ;
        RECT 0.0000 0.1280 0.2520 0.1600 ;
    END
  END VDD
  PIN VSS
    DIRECTION INOUT ;
    USE GROUND ;
    SHAPE ABUTMENT ;
    PORT
      LAYER BPR ;
        RECT 0.0000 -0.0160 0.2520 0.0160 ;
    END
  END VSS
  OBS
    LAYER M0 ;
      RECT 0.0095 0.0400 0.2005 0.0520 ;
  END
END gt2_6t_oai32_x1_w13_lvt

MACRO gt2_6t_oai33_x1_w13_lvt
  CLASS CORE ;
  ORIGIN 0 0 ;
  FOREIGN gt2_6t_oai33_x1_w13_lvt 0 0 ;
  SIZE 0.2940 BY 0.1440 ;
  SYMMETRY X Y ;
  SITE gt2_6t ;
  PIN A1
    DIRECTION INPUT ;
    USE SIGNAL ;
    PORT
      LAYER M0 ;
        RECT 0.1470 0.0920 0.1795 0.1040 ;
    END
  END A1
  PIN A2
    DIRECTION INPUT ;
    USE SIGNAL ;
    PORT
      LAYER M0 ;
        RECT 0.2405 0.1160 0.2730 0.1280 ;
    END
  END A2
  PIN A3
    DIRECTION INPUT ;
    USE SIGNAL ;
    PORT
      LAYER M0 ;
        RECT 0.1985 0.0920 0.2310 0.1040 ;
    END
  END A3
  PIN B1
    DIRECTION INPUT ;
    USE SIGNAL ;
    PORT
      LAYER M0 ;
        RECT 0.0725 0.1160 0.1050 0.1280 ;
    END
  END B1
  PIN B2
    DIRECTION INPUT ;
    USE SIGNAL ;
    PORT
      LAYER M0 ;
        RECT 0.1145 0.0160 0.1470 0.0280 ;
    END
  END B2
  PIN B3
    DIRECTION INPUT ;
    USE SIGNAL ;
    PORT
      LAYER M0 ;
        RECT 0.0210 0.0920 0.0535 0.1040 ;
    END
  END B3
  PIN Y
    DIRECTION OUTPUT ;
    USE SIGNAL ;
    PORT
      LAYER M1 ;
        RECT 0.1960 0.0110 0.2100 0.1330 ;
      LAYER M0 ;
        RECT 0.1775 0.0160 0.2845 0.0280 ;
        RECT 0.1355 0.1160 0.2180 0.1280 ;
      LAYER V0 ;
        RECT 0.1960 0.0160 0.2100 0.0280 ;
        RECT 0.1960 0.1160 0.2100 0.1280 ;
    END
  END Y
  PIN VDD
    DIRECTION INOUT ;
    USE POWER ;
    SHAPE ABUTMENT ;
    PORT
      LAYER BPR ;
        RECT 0.0000 0.1280 0.2940 0.1600 ;
    END
  END VDD
  PIN VSS
    DIRECTION INOUT ;
    USE GROUND ;
    SHAPE ABUTMENT ;
    PORT
      LAYER BPR ;
        RECT 0.0000 -0.0160 0.2940 0.0160 ;
    END
  END VSS
  OBS
    LAYER M0 ;
      RECT 0.0515 0.0400 0.2425 0.0520 ;
  END
END gt2_6t_oai33_x1_w13_lvt

MACRO gt2_6t_or2_x1_w13_lvt
  CLASS CORE ;
  ORIGIN 0 0 ;
  FOREIGN gt2_6t_or2_x1_w13_lvt 0 0 ;
  SIZE 0.1680 BY 0.1440 ;
  SYMMETRY X Y ;
  SITE gt2_6t ;
  PIN A
    DIRECTION INPUT ;
    USE SIGNAL ;
    PORT
      LAYER M0 ;
        RECT 0.0725 0.1160 0.1050 0.1280 ;
    END
  END A
  PIN B
    DIRECTION INPUT ;
    USE SIGNAL ;
    PORT
      LAYER M0 ;
        RECT 0.0210 0.0160 0.0535 0.0280 ;
    END
  END B
  PIN Y
    DIRECTION OUTPUT ;
    USE SIGNAL ;
    PORT
      LAYER M0 ;
        RECT 0.1260 0.0160 0.1585 0.0280 ;
    END
  END Y
  PIN VDD
    DIRECTION INOUT ;
    USE POWER ;
    SHAPE ABUTMENT ;
    PORT
      LAYER BPR ;
        RECT 0.0000 0.1280 0.1680 0.1600 ;
    END
  END VDD
  PIN VSS
    DIRECTION INOUT ;
    USE GROUND ;
    SHAPE ABUTMENT ;
    PORT
      LAYER BPR ;
        RECT 0.0000 -0.0160 0.1680 0.0160 ;
    END
  END VSS
  OBS
    LAYER M0 ;
      RECT 0.0515 0.0400 0.1375 0.0520 ;
      RECT 0.0095 0.0920 0.1375 0.1040 ;
  END
END gt2_6t_or2_x1_w13_lvt

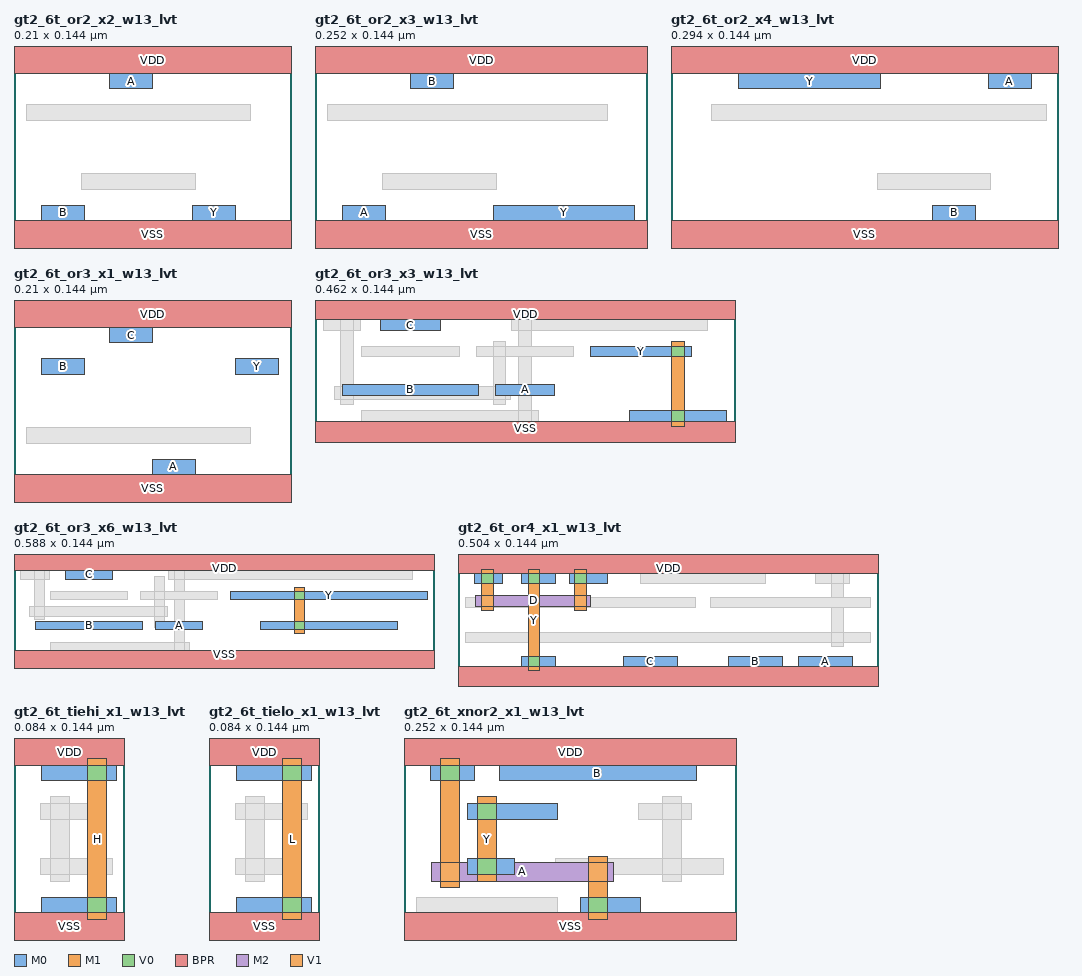
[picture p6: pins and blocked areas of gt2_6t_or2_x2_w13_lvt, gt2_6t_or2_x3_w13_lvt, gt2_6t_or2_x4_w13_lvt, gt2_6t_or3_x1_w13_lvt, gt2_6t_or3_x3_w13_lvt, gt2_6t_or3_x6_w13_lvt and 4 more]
MACRO gt2_6t_or2_x2_w13_lvt
  CLASS CORE ;
  ORIGIN 0 0 ;
  FOREIGN gt2_6t_or2_x2_w13_lvt 0 0 ;
  SIZE 0.2100 BY 0.1440 ;
  SYMMETRY X Y ;
  SITE gt2_6t ;
  PIN A
    DIRECTION INPUT ;
    USE SIGNAL ;
    PORT
      LAYER M0 ;
        RECT 0.0725 0.1160 0.1050 0.1280 ;
    END
  END A
  PIN B
    DIRECTION INPUT ;
    USE SIGNAL ;
    PORT
      LAYER M0 ;
        RECT 0.0210 0.0160 0.0535 0.0280 ;
    END
  END B
  PIN Y
    DIRECTION OUTPUT ;
    USE SIGNAL ;
    PORT
      LAYER M0 ;
        RECT 0.1355 0.0160 0.1680 0.0280 ;
    END
  END Y
  PIN VDD
    DIRECTION INOUT ;
    USE POWER ;
    SHAPE ABUTMENT ;
    PORT
      LAYER BPR ;
        RECT 0.0000 0.1280 0.2100 0.1600 ;
    END
  END VDD
  PIN VSS
    DIRECTION INOUT ;
    USE GROUND ;
    SHAPE ABUTMENT ;
    PORT
      LAYER BPR ;
        RECT 0.0000 -0.0160 0.2100 0.0160 ;
    END
  END VSS
  OBS
    LAYER M0 ;
      RECT 0.0515 0.0400 0.1375 0.0520 ;
      RECT 0.0095 0.0920 0.1795 0.1040 ;
  END
END gt2_6t_or2_x2_w13_lvt

MACRO gt2_6t_or2_x3_w13_lvt
  CLASS CORE ;
  ORIGIN 0 0 ;
  FOREIGN gt2_6t_or2_x3_w13_lvt 0 0 ;
  SIZE 0.2520 BY 0.1440 ;
  SYMMETRY X Y ;
  SITE gt2_6t ;
  PIN A
    DIRECTION INPUT ;
    USE SIGNAL ;
    PORT
      LAYER M0 ;
        RECT 0.0210 0.0160 0.0535 0.0280 ;
    END
  END A
  PIN B
    DIRECTION INPUT ;
    USE SIGNAL ;
    PORT
      LAYER M0 ;
        RECT 0.0725 0.1160 0.1050 0.1280 ;
    END
  END B
  PIN Y
    DIRECTION OUTPUT ;
    USE SIGNAL ;
    PORT
      LAYER M0 ;
        RECT 0.1355 0.0160 0.2425 0.0280 ;
    END
  END Y
  PIN VDD
    DIRECTION INOUT ;
    USE POWER ;
    SHAPE ABUTMENT ;
    PORT
      LAYER BPR ;
        RECT 0.0000 0.1280 0.2520 0.1600 ;
    END
  END VDD
  PIN VSS
    DIRECTION INOUT ;
    USE GROUND ;
    SHAPE ABUTMENT ;
    PORT
      LAYER BPR ;
        RECT 0.0000 -0.0160 0.2520 0.0160 ;
    END
  END VSS
  OBS
    LAYER M0 ;
      RECT 0.0515 0.0400 0.1375 0.0520 ;
      RECT 0.0095 0.0920 0.2215 0.1040 ;
  END
END gt2_6t_or2_x3_w13_lvt

MACRO gt2_6t_or2_x4_w13_lvt
  CLASS CORE ;
  ORIGIN 0 0 ;
  FOREIGN gt2_6t_or2_x4_w13_lvt 0 0 ;
  SIZE 0.2940 BY 0.1440 ;
  SYMMETRY X Y ;
  SITE gt2_6t ;
  PIN A
    DIRECTION INPUT ;
    USE SIGNAL ;
    PORT
      LAYER M0 ;
        RECT 0.2405 0.1160 0.2730 0.1280 ;
    END
  END A
  PIN B
    DIRECTION INPUT ;
    USE SIGNAL ;
    PORT
      LAYER M0 ;
        RECT 0.1985 0.0160 0.2310 0.0280 ;
    END
  END B
  PIN Y
    DIRECTION OUTPUT ;
    USE SIGNAL ;
    PORT
      LAYER M0 ;
        RECT 0.0515 0.1160 0.1585 0.1280 ;
    END
  END Y
  PIN VDD
    DIRECTION INOUT ;
    USE POWER ;
    SHAPE ABUTMENT ;
    PORT
      LAYER BPR ;
        RECT 0.0000 0.1280 0.2940 0.1600 ;
    END
  END VDD
  PIN VSS
    DIRECTION INOUT ;
    USE GROUND ;
    SHAPE ABUTMENT ;
    PORT
      LAYER BPR ;
        RECT 0.0000 -0.0160 0.2940 0.0160 ;
    END
  END VSS
  OBS
    LAYER M0 ;
      RECT 0.1565 0.0400 0.2425 0.0520 ;
      RECT 0.0305 0.0920 0.2845 0.1040 ;
  END
END gt2_6t_or2_x4_w13_lvt

MACRO gt2_6t_or3_x1_w13_lvt
  CLASS CORE ;
  ORIGIN 0 0 ;
  FOREIGN gt2_6t_or3_x1_w13_lvt 0 0 ;
  SIZE 0.2100 BY 0.1440 ;
  SYMMETRY X Y ;
  SITE gt2_6t ;
  PIN A
    DIRECTION INPUT ;
    USE SIGNAL ;
    PORT
      LAYER M0 ;
        RECT 0.1050 0.0160 0.1375 0.0280 ;
    END
  END A
  PIN B
    DIRECTION INPUT ;
    USE SIGNAL ;
    PORT
      LAYER M0 ;
        RECT 0.0210 0.0920 0.0535 0.1040 ;
    END
  END B
  PIN C
    DIRECTION INPUT ;
    USE SIGNAL ;
    PORT
      LAYER M0 ;
        RECT 0.0725 0.1160 0.1050 0.1280 ;
    END
  END C
  PIN Y
    DIRECTION OUTPUT ;
    USE SIGNAL ;
    PORT
      LAYER M0 ;
        RECT 0.1680 0.0920 0.2005 0.1040 ;
    END
  END Y
  PIN VDD
    DIRECTION INOUT ;
    USE POWER ;
    SHAPE ABUTMENT ;
    PORT
      LAYER BPR ;
        RECT 0.0000 0.1280 0.2100 0.1600 ;
    END
  END VDD
  PIN VSS
    DIRECTION INOUT ;
    USE GROUND ;
    SHAPE ABUTMENT ;
    PORT
      LAYER BPR ;
        RECT 0.0000 -0.0160 0.2100 0.0160 ;
    END
  END VSS
  OBS
    LAYER M0 ;
      RECT 0.0095 0.0400 0.1795 0.0520 ;
  END
END gt2_6t_or3_x1_w13_lvt

MACRO gt2_6t_or3_x3_w13_lvt
  CLASS CORE ;
  ORIGIN 0 0 ;
  FOREIGN gt2_6t_or3_x3_w13_lvt 0 0 ;
  SIZE 0.4620 BY 0.1440 ;
  SYMMETRY X Y ;
  SITE gt2_6t ;
  PIN A
    DIRECTION INPUT ;
    USE SIGNAL ;
    PORT
      LAYER M0 ;
        RECT 0.1985 0.0450 0.2635 0.0570 ;
    END
  END A
  PIN B
    DIRECTION INPUT ;
    USE SIGNAL ;
    PORT
      LAYER M0 ;
        RECT 0.0305 0.0450 0.1795 0.0570 ;
    END
  END B
  PIN C
    DIRECTION INPUT ;
    USE SIGNAL ;
    PORT
      LAYER M0 ;
        RECT 0.0725 0.1160 0.1375 0.1280 ;
    END
  END C
  PIN Y
    DIRECTION OUTPUT ;
    USE SIGNAL ;
    PORT
      LAYER M1 ;
        RECT 0.3920 0.0110 0.4060 0.1040 ;
      LAYER M0 ;
        RECT 0.3455 0.0160 0.4525 0.0280 ;
        RECT 0.3035 0.0870 0.4140 0.0990 ;
      LAYER V0 ;
        RECT 0.3920 0.0160 0.4060 0.0280 ;
        RECT 0.3920 0.0870 0.4060 0.0990 ;
    END
  END Y
  PIN VDD
    DIRECTION INOUT ;
    USE POWER ;
    SHAPE ABUTMENT ;
    PORT
      LAYER BPR ;
        RECT 0.0000 0.1280 0.4620 0.1600 ;
    END
  END VDD
  PIN VSS
    DIRECTION INOUT ;
    USE GROUND ;
    SHAPE ABUTMENT ;
    PORT
      LAYER BPR ;
        RECT 0.0000 -0.0160 0.4620 0.0160 ;
    END
  END VSS
  OBS
    LAYER M2 ;
      RECT 0.0210 0.0400 0.2150 0.0540 ;
    LAYER M1 ;
      RECT 0.2240 0.0110 0.2380 0.1330 ;
      RECT 0.1960 0.0350 0.2100 0.1040 ;
      RECT 0.0280 0.0350 0.0420 0.1330 ;
    LAYER M0 ;
      RECT 0.0515 0.0160 0.2460 0.0280 ;
      RECT 0.2160 0.1160 0.4315 0.1280 ;
      RECT 0.0515 0.0870 0.1585 0.0990 ;
      RECT 0.1775 0.0870 0.2845 0.0990 ;
      RECT 0.0095 0.1160 0.0500 0.1280 ;
    LAYER V1 ;
      RECT 0.0280 0.0400 0.0420 0.0540 ;
      RECT 0.1960 0.0400 0.2100 0.0540 ;
    LAYER V0 ;
      RECT 0.2240 0.0160 0.2380 0.0280 ;
      RECT 0.2240 0.1160 0.2380 0.1280 ;
      RECT 0.1960 0.0870 0.2100 0.0990 ;
      RECT 0.0280 0.1160 0.0420 0.1280 ;
  END
END gt2_6t_or3_x3_w13_lvt

MACRO gt2_6t_or3_x6_w13_lvt
  CLASS CORE ;
  ORIGIN 0 0 ;
  FOREIGN gt2_6t_or3_x6_w13_lvt 0 0 ;
  SIZE 0.5880 BY 0.1440 ;
  SYMMETRY X Y ;
  SITE gt2_6t ;
  PIN A
    DIRECTION INPUT ;
    USE SIGNAL ;
    PORT
      LAYER M0 ;
        RECT 0.1985 0.0450 0.2635 0.0570 ;
    END
  END A
  PIN B
    DIRECTION INPUT ;
    USE SIGNAL ;
    PORT
      LAYER M0 ;
        RECT 0.0305 0.0450 0.1795 0.0570 ;
    END
  END B
  PIN C
    DIRECTION INPUT ;
    USE SIGNAL ;
    PORT
      LAYER M0 ;
        RECT 0.0725 0.1160 0.1375 0.1280 ;
    END
  END C
  PIN Y
    DIRECTION OUTPUT ;
    USE SIGNAL ;
    PORT
      LAYER M1 ;
        RECT 0.3920 0.0400 0.4060 0.1040 ;
      LAYER M0 ;
        RECT 0.3455 0.0450 0.5365 0.0570 ;
        RECT 0.3035 0.0870 0.5785 0.0990 ;
      LAYER V0 ;
        RECT 0.3920 0.0450 0.4060 0.0570 ;
        RECT 0.3920 0.0870 0.4060 0.0990 ;
    END
  END Y
  PIN VDD
    DIRECTION INOUT ;
    USE POWER ;
    SHAPE ABUTMENT ;
    PORT
      LAYER BPR ;
        RECT 0.0000 0.1280 0.5880 0.1600 ;
    END
  END VDD
  PIN VSS
    DIRECTION INOUT ;
    USE GROUND ;
    SHAPE ABUTMENT ;
    PORT
      LAYER BPR ;
        RECT 0.0000 -0.0160 0.5880 0.0160 ;
    END
  END VSS
  OBS
    LAYER M2 ;
      RECT 0.0210 0.0640 0.2150 0.0780 ;
    LAYER M1 ;
      RECT 0.2240 0.0110 0.2380 0.1330 ;
      RECT 0.1960 0.0480 0.2100 0.1200 ;
      RECT 0.0280 0.0590 0.0420 0.1330 ;
    LAYER M0 ;
      RECT 0.0515 0.0160 0.2460 0.0280 ;
      RECT 0.2160 0.1160 0.5575 0.1280 ;
      RECT 0.0515 0.0870 0.1585 0.0990 ;
      RECT 0.1775 0.0870 0.2845 0.0990 ;
      RECT 0.0095 0.1160 0.0500 0.1280 ;
    LAYER V1 ;
      RECT 0.0280 0.0640 0.0420 0.0780 ;
      RECT 0.1960 0.0640 0.2100 0.0780 ;
    LAYER V0 ;
      RECT 0.2240 0.0160 0.2380 0.0280 ;
      RECT 0.2240 0.1160 0.2380 0.1280 ;
      RECT 0.1960 0.0870 0.2100 0.0990 ;
      RECT 0.0280 0.1160 0.0420 0.1280 ;
  END
END gt2_6t_or3_x6_w13_lvt

MACRO gt2_6t_or4_x1_w13_lvt
  CLASS CORE ;
  ORIGIN 0 0 ;
  FOREIGN gt2_6t_or4_x1_w13_lvt 0 0 ;
  SIZE 0.5040 BY 0.1440 ;
  SYMMETRY X Y ;
  SITE gt2_6t ;
  PIN A
    DIRECTION INPUT ;
    USE SIGNAL ;
    PORT
      LAYER M0 ;
        RECT 0.4085 0.0160 0.4735 0.0280 ;
    END
  END A
  PIN B
    DIRECTION INPUT ;
    USE SIGNAL ;
    PORT
      LAYER M0 ;
        RECT 0.3245 0.0160 0.3895 0.0280 ;
    END
  END B
  PIN C
    DIRECTION INPUT ;
    USE SIGNAL ;
    PORT
      LAYER M0 ;
        RECT 0.1985 0.0160 0.2635 0.0280 ;
    END
  END C
  PIN D
    DIRECTION INPUT ;
    USE SIGNAL ;
    PORT
      LAYER M2 ;
        RECT 0.0210 0.0880 0.1590 0.1020 ;
      LAYER M1 ;
        RECT 0.0280 0.0830 0.0420 0.1330 ;
        RECT 0.1400 0.0830 0.1540 0.1330 ;
      LAYER M0 ;
        RECT 0.0200 0.1160 0.0535 0.1280 ;
        RECT 0.1335 0.1160 0.1795 0.1280 ;
      LAYER V1 ;
        RECT 0.0280 0.0880 0.0420 0.1020 ;
        RECT 0.1400 0.0880 0.1540 0.1020 ;
      LAYER V0 ;
        RECT 0.0280 0.1160 0.0420 0.1280 ;
        RECT 0.1400 0.1160 0.1540 0.1280 ;
    END
  END D
  PIN Y
    DIRECTION OUTPUT ;
    USE SIGNAL ;
    PORT
      LAYER M1 ;
        RECT 0.0840 0.0110 0.0980 0.1330 ;
      LAYER M0 ;
        RECT 0.0760 0.0160 0.1165 0.0280 ;
        RECT 0.0760 0.1160 0.1165 0.1280 ;
      LAYER V0 ;
        RECT 0.0840 0.0160 0.0980 0.0280 ;
        RECT 0.0840 0.1160 0.0980 0.1280 ;
    END
  END Y
  PIN VDD
    DIRECTION INOUT ;
    USE POWER ;
    SHAPE ABUTMENT ;
    PORT
      LAYER BPR ;
        RECT 0.0000 0.1280 0.5040 0.1600 ;
    END
  END VDD
  PIN VSS
    DIRECTION INOUT ;
    USE GROUND ;
    SHAPE ABUTMENT ;
    PORT
      LAYER BPR ;
        RECT 0.0000 -0.0160 0.5040 0.0160 ;
    END
  END VSS
  OBS
    LAYER M1 ;
      RECT 0.4480 0.0400 0.4620 0.1330 ;
    LAYER M0 ;
      RECT 0.0095 0.0870 0.2845 0.0990 ;
      RECT 0.0095 0.0450 0.4945 0.0570 ;
      RECT 0.4295 0.1160 0.4700 0.1280 ;
      RECT 0.3035 0.0870 0.4945 0.0990 ;
      RECT 0.2195 0.1160 0.3685 0.1280 ;
    LAYER V0 ;
      RECT 0.4480 0.0450 0.4620 0.0570 ;
      RECT 0.4480 0.1160 0.4620 0.1280 ;
  END
END gt2_6t_or4_x1_w13_lvt


MACRO gt2_6t_tiehi_x1_w13_lvt
  CLASS CORE ;
  ORIGIN 0 0 ;
  FOREIGN gt2_6t_tiehi_x1_w13_lvt 0 0 ;
  SIZE 0.0840 BY 0.1440 ;
  SYMMETRY X Y ;
  SITE gt2_6t ;
  PIN H
    DIRECTION OUTPUT ;
    USE SIGNAL ;
    PORT
      LAYER M1 ;
        RECT 0.0560 0.0110 0.0700 0.1330 ;
      LAYER M0 ;
        RECT 0.0210 0.0160 0.0780 0.0280 ;
        RECT 0.0210 0.1160 0.0780 0.1280 ;
      LAYER V0 ;
        RECT 0.0560 0.0160 0.0700 0.0280 ;
        RECT 0.0560 0.1160 0.0700 0.1280 ;
    END
  END H
  PIN VDD
    DIRECTION INOUT ;
    USE POWER ;
    SHAPE ABUTMENT ;
    PORT
      LAYER BPR ;
        RECT 0.0000 0.1280 0.0840 0.1600 ;
    END
  END VDD
  PIN VSS
    DIRECTION INOUT ;
    USE GROUND ;
    SHAPE ABUTMENT ;
    PORT
      LAYER BPR ;
        RECT 0.0000 -0.0160 0.0840 0.0160 ;
    END
  END VSS
  OBS
    LAYER M1 ;
      RECT 0.0280 0.0400 0.0420 0.1040 ;
    LAYER M0 ;
      RECT 0.0200 0.0450 0.0745 0.0570 ;
      RECT 0.0200 0.0870 0.0630 0.0990 ;
    LAYER V0 ;
      RECT 0.0280 0.0450 0.0420 0.0570 ;
      RECT 0.0280 0.0870 0.0420 0.0990 ;
  END
END gt2_6t_tiehi_x1_w13_lvt

MACRO gt2_6t_tielo_x1_w13_lvt
  CLASS CORE ;
  ORIGIN 0 0 ;
  FOREIGN gt2_6t_tielo_x1_w13_lvt 0 0 ;
  SIZE 0.0840 BY 0.1440 ;
  SYMMETRY X Y ;
  SITE gt2_6t ;
  PIN L
    DIRECTION OUTPUT ;
    USE SIGNAL ;
    PORT
      LAYER M1 ;
        RECT 0.0560 0.0110 0.0700 0.1330 ;
      LAYER M0 ;
        RECT 0.0210 0.0160 0.0780 0.0280 ;
        RECT 0.0210 0.1160 0.0780 0.1280 ;
      LAYER V0 ;
        RECT 0.0560 0.0160 0.0700 0.0280 ;
        RECT 0.0560 0.1160 0.0700 0.1280 ;
    END
  END L
  PIN VDD
    DIRECTION INOUT ;
    USE POWER ;
    SHAPE ABUTMENT ;
    PORT
      LAYER BPR ;
        RECT 0.0000 0.1280 0.0840 0.1600 ;
    END
  END VDD
  PIN VSS
    DIRECTION INOUT ;
    USE GROUND ;
    SHAPE ABUTMENT ;
    PORT
      LAYER BPR ;
        RECT 0.0000 -0.0160 0.0840 0.0160 ;
    END
  END VSS
  OBS
    LAYER M1 ;
      RECT 0.0280 0.0400 0.0420 0.1040 ;
    LAYER M0 ;
      RECT 0.0200 0.0450 0.0630 0.0570 ;
      RECT 0.0200 0.0870 0.0745 0.0990 ;
    LAYER V0 ;
      RECT 0.0280 0.0450 0.0420 0.0570 ;
      RECT 0.0280 0.0870 0.0420 0.0990 ;
  END
END gt2_6t_tielo_x1_w13_lvt

MACRO gt2_6t_xnor2_x1_w13_lvt
  CLASS CORE ;
  ORIGIN 0 0 ;
  FOREIGN gt2_6t_xnor2_x1_w13_lvt 0 0 ;
  SIZE 0.2520 BY 0.1440 ;
  SYMMETRY X Y ;
  SITE gt2_6t ;
  PIN A
    DIRECTION INPUT ;
    USE SIGNAL ;
    PORT
      LAYER M2 ;
        RECT 0.0210 0.0400 0.1590 0.0540 ;
      LAYER M1 ;
        RECT 0.1400 0.0110 0.1540 0.0590 ;
        RECT 0.0280 0.0350 0.0420 0.1330 ;
      LAYER M0 ;
        RECT 0.1335 0.0160 0.1795 0.0280 ;
        RECT 0.0200 0.1160 0.0535 0.1280 ;
      LAYER V1 ;
        RECT 0.0280 0.0400 0.0420 0.0540 ;
        RECT 0.1400 0.0400 0.1540 0.0540 ;
      LAYER V0 ;
        RECT 0.1400 0.0160 0.1540 0.0280 ;
        RECT 0.0280 0.1160 0.0420 0.1280 ;
    END
  END A
  PIN B
    DIRECTION INPUT ;
    USE SIGNAL ;
    PORT
      LAYER M0 ;
        RECT 0.0725 0.1160 0.2215 0.1280 ;
    END
  END B
  PIN Y
    DIRECTION OUTPUT ;
    USE SIGNAL ;
    PORT
      LAYER M1 ;
        RECT 0.0560 0.0400 0.0700 0.1040 ;
      LAYER M0 ;
        RECT 0.0480 0.0450 0.0840 0.0570 ;
        RECT 0.0480 0.0870 0.1165 0.0990 ;
      LAYER V0 ;
        RECT 0.0560 0.0450 0.0700 0.0570 ;
        RECT 0.0560 0.0870 0.0700 0.0990 ;
    END
  END Y
  PIN VDD
    DIRECTION INOUT ;
    USE POWER ;
    SHAPE ABUTMENT ;
    PORT
      LAYER BPR ;
        RECT 0.0000 0.1280 0.2520 0.1600 ;
    END
  END VDD
  PIN VSS
    DIRECTION INOUT ;
    USE GROUND ;
    SHAPE ABUTMENT ;
    PORT
      LAYER BPR ;
        RECT 0.0000 -0.0160 0.2520 0.0160 ;
    END
  END VSS
  OBS
    LAYER M1 ;
      RECT 0.1960 0.0400 0.2100 0.1040 ;
    LAYER M0 ;
      RECT 0.0095 0.0160 0.1165 0.0280 ;
      RECT 0.1145 0.0450 0.2425 0.0570 ;
      RECT 0.1775 0.0870 0.2180 0.0990 ;
    LAYER V0 ;
      RECT 0.1960 0.0450 0.2100 0.0570 ;
      RECT 0.1960 0.0870 0.2100 0.0990 ;
  END
END gt2_6t_xnor2_x1_w13_lvt

END LIBRARY
